VERSION 5.8 ;
BUSBITCHARS "[]" ;
DIVIDERCHAR "/" ;
UNITS
    DATABASE MICRONS 1000 ;
END UNITS

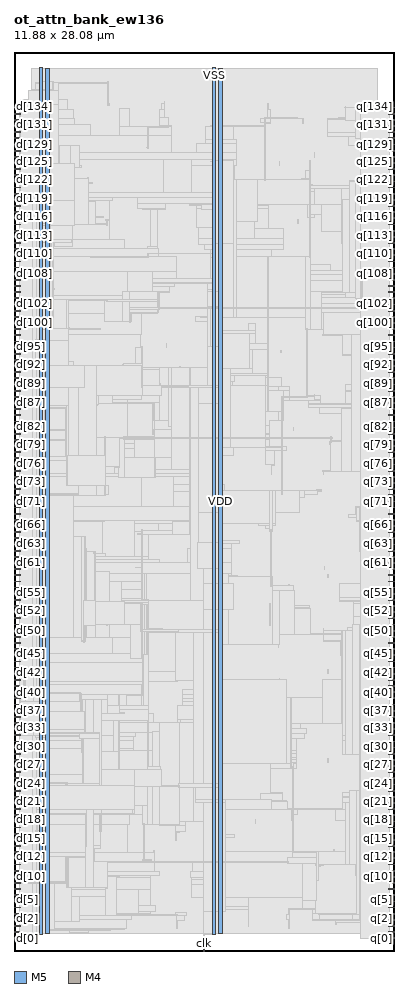
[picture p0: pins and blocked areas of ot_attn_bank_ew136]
MACRO ot_attn_bank_ew136
  FOREIGN ot_attn_bank_ew136 0 0 ;
  CLASS BLOCK ;
  SIZE 11.88 BY 28.08 ;
  PIN clk
    DIRECTION INPUT ;
    USE SIGNAL ;
    PORT
      LAYER M5 ;
        RECT  5.904 0 5.928 0.192 ;
    END
  END clk
  PIN d[0]
    DIRECTION INPUT ;
    USE SIGNAL ;
    PORT
      LAYER M4 ;
        RECT  0 0.384 0.192 0.408 ;
    END
  END d[0]
  PIN d[100]
    DIRECTION INPUT ;
    USE SIGNAL ;
    PORT
      LAYER M4 ;
        RECT  0 19.584 0.192 19.608 ;
    END
  END d[100]
  PIN d[101]
    DIRECTION INPUT ;
    USE SIGNAL ;
    PORT
      LAYER M4 ;
        RECT  0 19.776 0.192 19.8 ;
    END
  END d[101]
  PIN d[102]
    DIRECTION INPUT ;
    USE SIGNAL ;
    PORT
      LAYER M4 ;
        RECT  0 19.968 0.192 19.992 ;
    END
  END d[102]
  PIN d[103]
    DIRECTION INPUT ;
    USE SIGNAL ;
    PORT
      LAYER M4 ;
        RECT  0 20.16 0.192 20.184 ;
    END
  END d[103]
  PIN d[104]
    DIRECTION INPUT ;
    USE SIGNAL ;
    PORT
      LAYER M4 ;
        RECT  0 20.352 0.192 20.376 ;
    END
  END d[104]
  PIN d[105]
    DIRECTION INPUT ;
    USE SIGNAL ;
    PORT
      LAYER M4 ;
        RECT  0 20.544 0.192 20.568 ;
    END
  END d[105]
  PIN d[106]
    DIRECTION INPUT ;
    USE SIGNAL ;
    PORT
      LAYER M4 ;
        RECT  0 20.736 0.192 20.76 ;
    END
  END d[106]
  PIN d[107]
    DIRECTION INPUT ;
    USE SIGNAL ;
    PORT
      LAYER M4 ;
        RECT  0 20.928 0.192 20.952 ;
    END
  END d[107]
  PIN d[108]
    DIRECTION INPUT ;
    USE SIGNAL ;
    PORT
      LAYER M4 ;
        RECT  0 21.12 0.192 21.144 ;
    END
  END d[108]
  PIN d[109]
    DIRECTION INPUT ;
    USE SIGNAL ;
    PORT
      LAYER M4 ;
        RECT  0 21.312 0.192 21.336 ;
    END
  END d[109]
  PIN d[10]
    DIRECTION INPUT ;
    USE SIGNAL ;
    PORT
      LAYER M4 ;
        RECT  0 2.304 0.192 2.328 ;
    END
  END d[10]
  PIN d[110]
    DIRECTION INPUT ;
    USE SIGNAL ;
    PORT
      LAYER M4 ;
        RECT  0 21.504 0.192 21.528 ;
    END
  END d[110]
  PIN d[111]
    DIRECTION INPUT ;
    USE SIGNAL ;
    PORT
      LAYER M4 ;
        RECT  0 21.696 0.192 21.72 ;
    END
  END d[111]
  PIN d[112]
    DIRECTION INPUT ;
    USE SIGNAL ;
    PORT
      LAYER M4 ;
        RECT  0 21.888 0.192 21.912 ;
    END
  END d[112]
  PIN d[113]
    DIRECTION INPUT ;
    USE SIGNAL ;
    PORT
      LAYER M4 ;
        RECT  0 22.08 0.192 22.104 ;
    END
  END d[113]
  PIN d[114]
    DIRECTION INPUT ;
    USE SIGNAL ;
    PORT
      LAYER M4 ;
        RECT  0 22.272 0.192 22.296 ;
    END
  END d[114]
  PIN d[115]
    DIRECTION INPUT ;
    USE SIGNAL ;
    PORT
      LAYER M4 ;
        RECT  0 22.464 0.192 22.488 ;
    END
  END d[115]
  PIN d[116]
    DIRECTION INPUT ;
    USE SIGNAL ;
    PORT
      LAYER M4 ;
        RECT  0 22.656 0.192 22.68 ;
    END
  END d[116]
  PIN d[117]
    DIRECTION INPUT ;
    USE SIGNAL ;
    PORT
      LAYER M4 ;
        RECT  0 22.848 0.192 22.872 ;
    END
  END d[117]
  PIN d[118]
    DIRECTION INPUT ;
    USE SIGNAL ;
    PORT
      LAYER M4 ;
        RECT  0 23.04 0.192 23.064 ;
    END
  END d[118]
  PIN d[119]
    DIRECTION INPUT ;
    USE SIGNAL ;
    PORT
      LAYER M4 ;
        RECT  0 23.232 0.192 23.256 ;
    END
  END d[119]
  PIN d[11]
    DIRECTION INPUT ;
    USE SIGNAL ;
    PORT
      LAYER M4 ;
        RECT  0 2.496 0.192 2.52 ;
    END
  END d[11]
  PIN d[120]
    DIRECTION INPUT ;
    USE SIGNAL ;
    PORT
      LAYER M4 ;
        RECT  0 23.424 0.192 23.448 ;
    END
  END d[120]
  PIN d[121]
    DIRECTION INPUT ;
    USE SIGNAL ;
    PORT
      LAYER M4 ;
        RECT  0 23.616 0.192 23.64 ;
    END
  END d[121]
  PIN d[122]
    DIRECTION INPUT ;
    USE SIGNAL ;
    PORT
      LAYER M4 ;
        RECT  0 23.808 0.192 23.832 ;
    END
  END d[122]
  PIN d[123]
    DIRECTION INPUT ;
    USE SIGNAL ;
    PORT
      LAYER M4 ;
        RECT  0 24 0.192 24.024 ;
    END
  END d[123]
  PIN d[124]
    DIRECTION INPUT ;
    USE SIGNAL ;
    PORT
      LAYER M4 ;
        RECT  0 24.192 0.192 24.216 ;
    END
  END d[124]
  PIN d[125]
    DIRECTION INPUT ;
    USE SIGNAL ;
    PORT
      LAYER M4 ;
        RECT  0 24.384 0.192 24.408 ;
    END
  END d[125]
  PIN d[126]
    DIRECTION INPUT ;
    USE SIGNAL ;
    PORT
      LAYER M4 ;
        RECT  0 24.576 0.192 24.6 ;
    END
  END d[126]
  PIN d[127]
    DIRECTION INPUT ;
    USE SIGNAL ;
    PORT
      LAYER M4 ;
        RECT  0 24.768 0.192 24.792 ;
    END
  END d[127]
  PIN d[128]
    DIRECTION INPUT ;
    USE SIGNAL ;
    PORT
      LAYER M4 ;
        RECT  0 24.96 0.192 24.984 ;
    END
  END d[128]
  PIN d[129]
    DIRECTION INPUT ;
    USE SIGNAL ;
    PORT
      LAYER M4 ;
        RECT  0 25.152 0.192 25.176 ;
    END
  END d[129]
  PIN d[12]
    DIRECTION INPUT ;
    USE SIGNAL ;
    PORT
      LAYER M4 ;
        RECT  0 2.688 0.192 2.712 ;
    END
  END d[12]
  PIN d[130]
    DIRECTION INPUT ;
    USE SIGNAL ;
    PORT
      LAYER M4 ;
        RECT  0 25.344 0.192 25.368 ;
    END
  END d[130]
  PIN d[131]
    DIRECTION INPUT ;
    USE SIGNAL ;
    PORT
      LAYER M4 ;
        RECT  0 25.536 0.192 25.56 ;
    END
  END d[131]
  PIN d[132]
    DIRECTION INPUT ;
    USE SIGNAL ;
    PORT
      LAYER M4 ;
        RECT  0 25.728 0.192 25.752 ;
    END
  END d[132]
  PIN d[133]
    DIRECTION INPUT ;
    USE SIGNAL ;
    PORT
      LAYER M4 ;
        RECT  0 25.92 0.192 25.944 ;
    END
  END d[133]
  PIN d[134]
    DIRECTION INPUT ;
    USE SIGNAL ;
    PORT
      LAYER M4 ;
        RECT  0 26.112 0.192 26.136 ;
    END
  END d[134]
  PIN d[135]
    DIRECTION INPUT ;
    USE SIGNAL ;
    PORT
      LAYER M4 ;
        RECT  0 26.304 0.192 26.328 ;
    END
  END d[135]
  PIN d[13]
    DIRECTION INPUT ;
    USE SIGNAL ;
    PORT
      LAYER M4 ;
        RECT  0 2.88 0.192 2.904 ;
    END
  END d[13]
  PIN d[14]
    DIRECTION INPUT ;
    USE SIGNAL ;
    PORT
      LAYER M4 ;
        RECT  0 3.072 0.192 3.096 ;
    END
  END d[14]
  PIN d[15]
    DIRECTION INPUT ;
    USE SIGNAL ;
    PORT
      LAYER M4 ;
        RECT  0 3.264 0.192 3.288 ;
    END
  END d[15]
  PIN d[16]
    DIRECTION INPUT ;
    USE SIGNAL ;
    PORT
      LAYER M4 ;
        RECT  0 3.456 0.192 3.48 ;
    END
  END d[16]
  PIN d[17]
    DIRECTION INPUT ;
    USE SIGNAL ;
    PORT
      LAYER M4 ;
        RECT  0 3.648 0.192 3.672 ;
    END
  END d[17]
  PIN d[18]
    DIRECTION INPUT ;
    USE SIGNAL ;
    PORT
      LAYER M4 ;
        RECT  0 3.84 0.192 3.864 ;
    END
  END d[18]
  PIN d[19]
    DIRECTION INPUT ;
    USE SIGNAL ;
    PORT
      LAYER M4 ;
        RECT  0 4.032 0.192 4.056 ;
    END
  END d[19]
  PIN d[1]
    DIRECTION INPUT ;
    USE SIGNAL ;
    PORT
      LAYER M4 ;
        RECT  0 0.576 0.192 0.6 ;
    END
  END d[1]
  PIN d[20]
    DIRECTION INPUT ;
    USE SIGNAL ;
    PORT
      LAYER M4 ;
        RECT  0 4.224 0.192 4.248 ;
    END
  END d[20]
  PIN d[21]
    DIRECTION INPUT ;
    USE SIGNAL ;
    PORT
      LAYER M4 ;
        RECT  0 4.416 0.192 4.44 ;
    END
  END d[21]
  PIN d[22]
    DIRECTION INPUT ;
    USE SIGNAL ;
    PORT
      LAYER M4 ;
        RECT  0 4.608 0.192 4.632 ;
    END
  END d[22]
  PIN d[23]
    DIRECTION INPUT ;
    USE SIGNAL ;
    PORT
      LAYER M4 ;
        RECT  0 4.8 0.192 4.824 ;
    END
  END d[23]
  PIN d[24]
    DIRECTION INPUT ;
    USE SIGNAL ;
    PORT
      LAYER M4 ;
        RECT  0 4.992 0.192 5.016 ;
    END
  END d[24]
  PIN d[25]
    DIRECTION INPUT ;
    USE SIGNAL ;
    PORT
      LAYER M4 ;
        RECT  0 5.184 0.192 5.208 ;
    END
  END d[25]
  PIN d[26]
    DIRECTION INPUT ;
    USE SIGNAL ;
    PORT
      LAYER M4 ;
        RECT  0 5.376 0.192 5.4 ;
    END
  END d[26]
  PIN d[27]
    DIRECTION INPUT ;
    USE SIGNAL ;
    PORT
      LAYER M4 ;
        RECT  0 5.568 0.192 5.592 ;
    END
  END d[27]
  PIN d[28]
    DIRECTION INPUT ;
    USE SIGNAL ;
    PORT
      LAYER M4 ;
        RECT  0 5.76 0.192 5.784 ;
    END
  END d[28]
  PIN d[29]
    DIRECTION INPUT ;
    USE SIGNAL ;
    PORT
      LAYER M4 ;
        RECT  0 5.952 0.192 5.976 ;
    END
  END d[29]
  PIN d[2]
    DIRECTION INPUT ;
    USE SIGNAL ;
    PORT
      LAYER M4 ;
        RECT  0 0.768 0.192 0.792 ;
    END
  END d[2]
  PIN d[30]
    DIRECTION INPUT ;
    USE SIGNAL ;
    PORT
      LAYER M4 ;
        RECT  0 6.144 0.192 6.168 ;
    END
  END d[30]
  PIN d[31]
    DIRECTION INPUT ;
    USE SIGNAL ;
    PORT
      LAYER M4 ;
        RECT  0 6.336 0.192 6.36 ;
    END
  END d[31]
  PIN d[32]
    DIRECTION INPUT ;
    USE SIGNAL ;
    PORT
      LAYER M4 ;
        RECT  0 6.528 0.192 6.552 ;
    END
  END d[32]
  PIN d[33]
    DIRECTION INPUT ;
    USE SIGNAL ;
    PORT
      LAYER M4 ;
        RECT  0 6.72 0.192 6.744 ;
    END
  END d[33]
  PIN d[34]
    DIRECTION INPUT ;
    USE SIGNAL ;
    PORT
      LAYER M4 ;
        RECT  0 6.912 0.192 6.936 ;
    END
  END d[34]
  PIN d[35]
    DIRECTION INPUT ;
    USE SIGNAL ;
    PORT
      LAYER M4 ;
        RECT  0 7.104 0.192 7.128 ;
    END
  END d[35]
  PIN d[36]
    DIRECTION INPUT ;
    USE SIGNAL ;
    PORT
      LAYER M4 ;
        RECT  0 7.296 0.192 7.32 ;
    END
  END d[36]
  PIN d[37]
    DIRECTION INPUT ;
    USE SIGNAL ;
    PORT
      LAYER M4 ;
        RECT  0 7.488 0.192 7.512 ;
    END
  END d[37]
  PIN d[38]
    DIRECTION INPUT ;
    USE SIGNAL ;
    PORT
      LAYER M4 ;
        RECT  0 7.68 0.192 7.704 ;
    END
  END d[38]
  PIN d[39]
    DIRECTION INPUT ;
    USE SIGNAL ;
    PORT
      LAYER M4 ;
        RECT  0 7.872 0.192 7.896 ;
    END
  END d[39]
  PIN d[3]
    DIRECTION INPUT ;
    USE SIGNAL ;
    PORT
      LAYER M4 ;
        RECT  0 0.96 0.192 0.984 ;
    END
  END d[3]
  PIN d[40]
    DIRECTION INPUT ;
    USE SIGNAL ;
    PORT
      LAYER M4 ;
        RECT  0 8.064 0.192 8.088 ;
    END
  END d[40]
  PIN d[41]
    DIRECTION INPUT ;
    USE SIGNAL ;
    PORT
      LAYER M4 ;
        RECT  0 8.256 0.192 8.28 ;
    END
  END d[41]
  PIN d[42]
    DIRECTION INPUT ;
    USE SIGNAL ;
    PORT
      LAYER M4 ;
        RECT  0 8.448 0.192 8.472 ;
    END
  END d[42]
  PIN d[43]
    DIRECTION INPUT ;
    USE SIGNAL ;
    PORT
      LAYER M4 ;
        RECT  0 8.64 0.192 8.664 ;
    END
  END d[43]
  PIN d[44]
    DIRECTION INPUT ;
    USE SIGNAL ;
    PORT
      LAYER M4 ;
        RECT  0 8.832 0.192 8.856 ;
    END
  END d[44]
  PIN d[45]
    DIRECTION INPUT ;
    USE SIGNAL ;
    PORT
      LAYER M4 ;
        RECT  0 9.024 0.192 9.048 ;
    END
  END d[45]
  PIN d[46]
    DIRECTION INPUT ;
    USE SIGNAL ;
    PORT
      LAYER M4 ;
        RECT  0 9.216 0.192 9.24 ;
    END
  END d[46]
  PIN d[47]
    DIRECTION INPUT ;
    USE SIGNAL ;
    PORT
      LAYER M4 ;
        RECT  0 9.408 0.192 9.432 ;
    END
  END d[47]
  PIN d[48]
    DIRECTION INPUT ;
    USE SIGNAL ;
    PORT
      LAYER M4 ;
        RECT  0 9.6 0.192 9.624 ;
    END
  END d[48]
  PIN d[49]
    DIRECTION INPUT ;
    USE SIGNAL ;
    PORT
      LAYER M4 ;
        RECT  0 9.792 0.192 9.816 ;
    END
  END d[49]
  PIN d[4]
    DIRECTION INPUT ;
    USE SIGNAL ;
    PORT
      LAYER M4 ;
        RECT  0 1.152 0.192 1.176 ;
    END
  END d[4]
  PIN d[50]
    DIRECTION INPUT ;
    USE SIGNAL ;
    PORT
      LAYER M4 ;
        RECT  0 9.984 0.192 10.008 ;
    END
  END d[50]
  PIN d[51]
    DIRECTION INPUT ;
    USE SIGNAL ;
    PORT
      LAYER M4 ;
        RECT  0 10.176 0.192 10.2 ;
    END
  END d[51]
  PIN d[52]
    DIRECTION INPUT ;
    USE SIGNAL ;
    PORT
      LAYER M4 ;
        RECT  0 10.368 0.192 10.392 ;
    END
  END d[52]
  PIN d[53]
    DIRECTION INPUT ;
    USE SIGNAL ;
    PORT
      LAYER M4 ;
        RECT  0 10.56 0.192 10.584 ;
    END
  END d[53]
  PIN d[54]
    DIRECTION INPUT ;
    USE SIGNAL ;
    PORT
      LAYER M4 ;
        RECT  0 10.752 0.192 10.776 ;
    END
  END d[54]
  PIN d[55]
    DIRECTION INPUT ;
    USE SIGNAL ;
    PORT
      LAYER M4 ;
        RECT  0 10.944 0.192 10.968 ;
    END
  END d[55]
  PIN d[56]
    DIRECTION INPUT ;
    USE SIGNAL ;
    PORT
      LAYER M4 ;
        RECT  0 11.136 0.192 11.16 ;
    END
  END d[56]
  PIN d[57]
    DIRECTION INPUT ;
    USE SIGNAL ;
    PORT
      LAYER M4 ;
        RECT  0 11.328 0.192 11.352 ;
    END
  END d[57]
  PIN d[58]
    DIRECTION INPUT ;
    USE SIGNAL ;
    PORT
      LAYER M4 ;
        RECT  0 11.52 0.192 11.544 ;
    END
  END d[58]
  PIN d[59]
    DIRECTION INPUT ;
    USE SIGNAL ;
    PORT
      LAYER M4 ;
        RECT  0 11.712 0.192 11.736 ;
    END
  END d[59]
  PIN d[5]
    DIRECTION INPUT ;
    USE SIGNAL ;
    PORT
      LAYER M4 ;
        RECT  0 1.344 0.192 1.368 ;
    END
  END d[5]
  PIN d[60]
    DIRECTION INPUT ;
    USE SIGNAL ;
    PORT
      LAYER M4 ;
        RECT  0 11.904 0.192 11.928 ;
    END
  END d[60]
  PIN d[61]
    DIRECTION INPUT ;
    USE SIGNAL ;
    PORT
      LAYER M4 ;
        RECT  0 12.096 0.192 12.12 ;
    END
  END d[61]
  PIN d[62]
    DIRECTION INPUT ;
    USE SIGNAL ;
    PORT
      LAYER M4 ;
        RECT  0 12.288 0.192 12.312 ;
    END
  END d[62]
  PIN d[63]
    DIRECTION INPUT ;
    USE SIGNAL ;
    PORT
      LAYER M4 ;
        RECT  0 12.48 0.192 12.504 ;
    END
  END d[63]
  PIN d[64]
    DIRECTION INPUT ;
    USE SIGNAL ;
    PORT
      LAYER M4 ;
        RECT  0 12.672 0.192 12.696 ;
    END
  END d[64]
  PIN d[65]
    DIRECTION INPUT ;
    USE SIGNAL ;
    PORT
      LAYER M4 ;
        RECT  0 12.864 0.192 12.888 ;
    END
  END d[65]
  PIN d[66]
    DIRECTION INPUT ;
    USE SIGNAL ;
    PORT
      LAYER M4 ;
        RECT  0 13.056 0.192 13.08 ;
    END
  END d[66]
  PIN d[67]
    DIRECTION INPUT ;
    USE SIGNAL ;
    PORT
      LAYER M4 ;
        RECT  0 13.248 0.192 13.272 ;
    END
  END d[67]
  PIN d[68]
    DIRECTION INPUT ;
    USE SIGNAL ;
    PORT
      LAYER M4 ;
        RECT  0 13.44 0.192 13.464 ;
    END
  END d[68]
  PIN d[69]
    DIRECTION INPUT ;
    USE SIGNAL ;
    PORT
      LAYER M4 ;
        RECT  0 13.632 0.192 13.656 ;
    END
  END d[69]
  PIN d[6]
    DIRECTION INPUT ;
    USE SIGNAL ;
    PORT
      LAYER M4 ;
        RECT  0 1.536 0.192 1.56 ;
    END
  END d[6]
  PIN d[70]
    DIRECTION INPUT ;
    USE SIGNAL ;
    PORT
      LAYER M4 ;
        RECT  0 13.824 0.192 13.848 ;
    END
  END d[70]
  PIN d[71]
    DIRECTION INPUT ;
    USE SIGNAL ;
    PORT
      LAYER M4 ;
        RECT  0 14.016 0.192 14.04 ;
    END
  END d[71]
  PIN d[72]
    DIRECTION INPUT ;
    USE SIGNAL ;
    PORT
      LAYER M4 ;
        RECT  0 14.208 0.192 14.232 ;
    END
  END d[72]
  PIN d[73]
    DIRECTION INPUT ;
    USE SIGNAL ;
    PORT
      LAYER M4 ;
        RECT  0 14.4 0.192 14.424 ;
    END
  END d[73]
  PIN d[74]
    DIRECTION INPUT ;
    USE SIGNAL ;
    PORT
      LAYER M4 ;
        RECT  0 14.592 0.192 14.616 ;
    END
  END d[74]
  PIN d[75]
    DIRECTION INPUT ;
    USE SIGNAL ;
    PORT
      LAYER M4 ;
        RECT  0 14.784 0.192 14.808 ;
    END
  END d[75]
  PIN d[76]
    DIRECTION INPUT ;
    USE SIGNAL ;
    PORT
      LAYER M4 ;
        RECT  0 14.976 0.192 15 ;
    END
  END d[76]
  PIN d[77]
    DIRECTION INPUT ;
    USE SIGNAL ;
    PORT
      LAYER M4 ;
        RECT  0 15.168 0.192 15.192 ;
    END
  END d[77]
  PIN d[78]
    DIRECTION INPUT ;
    USE SIGNAL ;
    PORT
      LAYER M4 ;
        RECT  0 15.36 0.192 15.384 ;
    END
  END d[78]
  PIN d[79]
    DIRECTION INPUT ;
    USE SIGNAL ;
    PORT
      LAYER M4 ;
        RECT  0 15.552 0.192 15.576 ;
    END
  END d[79]
  PIN d[7]
    DIRECTION INPUT ;
    USE SIGNAL ;
    PORT
      LAYER M4 ;
        RECT  0 1.728 0.192 1.752 ;
    END
  END d[7]
  PIN d[80]
    DIRECTION INPUT ;
    USE SIGNAL ;
    PORT
      LAYER M4 ;
        RECT  0 15.744 0.192 15.768 ;
    END
  END d[80]
  PIN d[81]
    DIRECTION INPUT ;
    USE SIGNAL ;
    PORT
      LAYER M4 ;
        RECT  0 15.936 0.192 15.96 ;
    END
  END d[81]
  PIN d[82]
    DIRECTION INPUT ;
    USE SIGNAL ;
    PORT
      LAYER M4 ;
        RECT  0 16.128 0.192 16.152 ;
    END
  END d[82]
  PIN d[83]
    DIRECTION INPUT ;
    USE SIGNAL ;
    PORT
      LAYER M4 ;
        RECT  0 16.32 0.192 16.344 ;
    END
  END d[83]
  PIN d[84]
    DIRECTION INPUT ;
    USE SIGNAL ;
    PORT
      LAYER M4 ;
        RECT  0 16.512 0.192 16.536 ;
    END
  END d[84]
  PIN d[85]
    DIRECTION INPUT ;
    USE SIGNAL ;
    PORT
      LAYER M4 ;
        RECT  0 16.704 0.192 16.728 ;
    END
  END d[85]
  PIN d[86]
    DIRECTION INPUT ;
    USE SIGNAL ;
    PORT
      LAYER M4 ;
        RECT  0 16.896 0.192 16.92 ;
    END
  END d[86]
  PIN d[87]
    DIRECTION INPUT ;
    USE SIGNAL ;
    PORT
      LAYER M4 ;
        RECT  0 17.088 0.192 17.112 ;
    END
  END d[87]
  PIN d[88]
    DIRECTION INPUT ;
    USE SIGNAL ;
    PORT
      LAYER M4 ;
        RECT  0 17.28 0.192 17.304 ;
    END
  END d[88]
  PIN d[89]
    DIRECTION INPUT ;
    USE SIGNAL ;
    PORT
      LAYER M4 ;
        RECT  0 17.472 0.192 17.496 ;
    END
  END d[89]
  PIN d[8]
    DIRECTION INPUT ;
    USE SIGNAL ;
    PORT
      LAYER M4 ;
        RECT  0 1.92 0.192 1.944 ;
    END
  END d[8]
  PIN d[90]
    DIRECTION INPUT ;
    USE SIGNAL ;
    PORT
      LAYER M4 ;
        RECT  0 17.664 0.192 17.688 ;
    END
  END d[90]
  PIN d[91]
    DIRECTION INPUT ;
    USE SIGNAL ;
    PORT
      LAYER M4 ;
        RECT  0 17.856 0.192 17.88 ;
    END
  END d[91]
  PIN d[92]
    DIRECTION INPUT ;
    USE SIGNAL ;
    PORT
      LAYER M4 ;
        RECT  0 18.048 0.192 18.072 ;
    END
  END d[92]
  PIN d[93]
    DIRECTION INPUT ;
    USE SIGNAL ;
    PORT
      LAYER M4 ;
        RECT  0 18.24 0.192 18.264 ;
    END
  END d[93]
  PIN d[94]
    DIRECTION INPUT ;
    USE SIGNAL ;
    PORT
      LAYER M4 ;
        RECT  0 18.432 0.192 18.456 ;
    END
  END d[94]
  PIN d[95]
    DIRECTION INPUT ;
    USE SIGNAL ;
    PORT
      LAYER M4 ;
        RECT  0 18.624 0.192 18.648 ;
    END
  END d[95]
  PIN d[96]
    DIRECTION INPUT ;
    USE SIGNAL ;
    PORT
      LAYER M4 ;
        RECT  0 18.816 0.192 18.84 ;
    END
  END d[96]
  PIN d[97]
    DIRECTION INPUT ;
    USE SIGNAL ;
    PORT
      LAYER M4 ;
        RECT  0 19.008 0.192 19.032 ;
    END
  END d[97]
  PIN d[98]
    DIRECTION INPUT ;
    USE SIGNAL ;
    PORT
      LAYER M4 ;
        RECT  0 19.2 0.192 19.224 ;
    END
  END d[98]
  PIN d[99]
    DIRECTION INPUT ;
    USE SIGNAL ;
    PORT
      LAYER M4 ;
        RECT  0 19.392 0.192 19.416 ;
    END
  END d[99]
  PIN d[9]
    DIRECTION INPUT ;
    USE SIGNAL ;
    PORT
      LAYER M4 ;
        RECT  0 2.112 0.192 2.136 ;
    END
  END d[9]
  PIN q[0]
    DIRECTION OUTPUT ;
    USE SIGNAL ;
    PORT
      LAYER M4 ;
        RECT  11.688 0.384 11.88 0.408 ;
    END
  END q[0]
  PIN q[100]
    DIRECTION OUTPUT ;
    USE SIGNAL ;
    PORT
      LAYER M4 ;
        RECT  11.688 19.584 11.88 19.608 ;
    END
  END q[100]
  PIN q[101]
    DIRECTION OUTPUT ;
    USE SIGNAL ;
    PORT
      LAYER M4 ;
        RECT  11.688 19.776 11.88 19.8 ;
    END
  END q[101]
  PIN q[102]
    DIRECTION OUTPUT ;
    USE SIGNAL ;
    PORT
      LAYER M4 ;
        RECT  11.688 19.968 11.88 19.992 ;
    END
  END q[102]
  PIN q[103]
    DIRECTION OUTPUT ;
    USE SIGNAL ;
    PORT
      LAYER M4 ;
        RECT  11.688 20.16 11.88 20.184 ;
    END
  END q[103]
  PIN q[104]
    DIRECTION OUTPUT ;
    USE SIGNAL ;
    PORT
      LAYER M4 ;
        RECT  11.688 20.352 11.88 20.376 ;
    END
  END q[104]
  PIN q[105]
    DIRECTION OUTPUT ;
    USE SIGNAL ;
    PORT
      LAYER M4 ;
        RECT  11.688 20.544 11.88 20.568 ;
    END
  END q[105]
  PIN q[106]
    DIRECTION OUTPUT ;
    USE SIGNAL ;
    PORT
      LAYER M4 ;
        RECT  11.688 20.736 11.88 20.76 ;
    END
  END q[106]
  PIN q[107]
    DIRECTION OUTPUT ;
    USE SIGNAL ;
    PORT
      LAYER M4 ;
        RECT  11.688 20.928 11.88 20.952 ;
    END
  END q[107]
  PIN q[108]
    DIRECTION OUTPUT ;
    USE SIGNAL ;
    PORT
      LAYER M4 ;
        RECT  11.688 21.12 11.88 21.144 ;
    END
  END q[108]
  PIN q[109]
    DIRECTION OUTPUT ;
    USE SIGNAL ;
    PORT
      LAYER M4 ;
        RECT  11.688 21.312 11.88 21.336 ;
    END
  END q[109]
  PIN q[10]
    DIRECTION OUTPUT ;
    USE SIGNAL ;
    PORT
      LAYER M4 ;
        RECT  11.688 2.304 11.88 2.328 ;
    END
  END q[10]
  PIN q[110]
    DIRECTION OUTPUT ;
    USE SIGNAL ;
    PORT
      LAYER M4 ;
        RECT  11.688 21.504 11.88 21.528 ;
    END
  END q[110]
  PIN q[111]
    DIRECTION OUTPUT ;
    USE SIGNAL ;
    PORT
      LAYER M4 ;
        RECT  11.688 21.696 11.88 21.72 ;
    END
  END q[111]
  PIN q[112]
    DIRECTION OUTPUT ;
    USE SIGNAL ;
    PORT
      LAYER M4 ;
        RECT  11.688 21.888 11.88 21.912 ;
    END
  END q[112]
  PIN q[113]
    DIRECTION OUTPUT ;
    USE SIGNAL ;
    PORT
      LAYER M4 ;
        RECT  11.688 22.08 11.88 22.104 ;
    END
  END q[113]
  PIN q[114]
    DIRECTION OUTPUT ;
    USE SIGNAL ;
    PORT
      LAYER M4 ;
        RECT  11.688 22.272 11.88 22.296 ;
    END
  END q[114]
  PIN q[115]
    DIRECTION OUTPUT ;
    USE SIGNAL ;
    PORT
      LAYER M4 ;
        RECT  11.688 22.464 11.88 22.488 ;
    END
  END q[115]
  PIN q[116]
    DIRECTION OUTPUT ;
    USE SIGNAL ;
    PORT
      LAYER M4 ;
        RECT  11.688 22.656 11.88 22.68 ;
    END
  END q[116]
  PIN q[117]
    DIRECTION OUTPUT ;
    USE SIGNAL ;
    PORT
      LAYER M4 ;
        RECT  11.688 22.848 11.88 22.872 ;
    END
  END q[117]
  PIN q[118]
    DIRECTION OUTPUT ;
    USE SIGNAL ;
    PORT
      LAYER M4 ;
        RECT  11.688 23.04 11.88 23.064 ;
    END
  END q[118]
  PIN q[119]
    DIRECTION OUTPUT ;
    USE SIGNAL ;
    PORT
      LAYER M4 ;
        RECT  11.688 23.232 11.88 23.256 ;
    END
  END q[119]
  PIN q[11]
    DIRECTION OUTPUT ;
    USE SIGNAL ;
    PORT
      LAYER M4 ;
        RECT  11.688 2.496 11.88 2.52 ;
    END
  END q[11]
  PIN q[120]
    DIRECTION OUTPUT ;
    USE SIGNAL ;
    PORT
      LAYER M4 ;
        RECT  11.688 23.424 11.88 23.448 ;
    END
  END q[120]
  PIN q[121]
    DIRECTION OUTPUT ;
    USE SIGNAL ;
    PORT
      LAYER M4 ;
        RECT  11.688 23.616 11.88 23.64 ;
    END
  END q[121]
  PIN q[122]
    DIRECTION OUTPUT ;
    USE SIGNAL ;
    PORT
      LAYER M4 ;
        RECT  11.688 23.808 11.88 23.832 ;
    END
  END q[122]
  PIN q[123]
    DIRECTION OUTPUT ;
    USE SIGNAL ;
    PORT
      LAYER M4 ;
        RECT  11.688 24 11.88 24.024 ;
    END
  END q[123]
  PIN q[124]
    DIRECTION OUTPUT ;
    USE SIGNAL ;
    PORT
      LAYER M4 ;
        RECT  11.688 24.192 11.88 24.216 ;
    END
  END q[124]
  PIN q[125]
    DIRECTION OUTPUT ;
    USE SIGNAL ;
    PORT
      LAYER M4 ;
        RECT  11.688 24.384 11.88 24.408 ;
    END
  END q[125]
  PIN q[126]
    DIRECTION OUTPUT ;
    USE SIGNAL ;
    PORT
      LAYER M4 ;
        RECT  11.688 24.576 11.88 24.6 ;
    END
  END q[126]
  PIN q[127]
    DIRECTION OUTPUT ;
    USE SIGNAL ;
    PORT
      LAYER M4 ;
        RECT  11.688 24.768 11.88 24.792 ;
    END
  END q[127]
  PIN q[128]
    DIRECTION OUTPUT ;
    USE SIGNAL ;
    PORT
      LAYER M4 ;
        RECT  11.688 24.96 11.88 24.984 ;
    END
  END q[128]
  PIN q[129]
    DIRECTION OUTPUT ;
    USE SIGNAL ;
    PORT
      LAYER M4 ;
        RECT  11.688 25.152 11.88 25.176 ;
    END
  END q[129]
  PIN q[12]
    DIRECTION OUTPUT ;
    USE SIGNAL ;
    PORT
      LAYER M4 ;
        RECT  11.688 2.688 11.88 2.712 ;
    END
  END q[12]
  PIN q[130]
    DIRECTION OUTPUT ;
    USE SIGNAL ;
    PORT
      LAYER M4 ;
        RECT  11.688 25.344 11.88 25.368 ;
    END
  END q[130]
  PIN q[131]
    DIRECTION OUTPUT ;
    USE SIGNAL ;
    PORT
      LAYER M4 ;
        RECT  11.688 25.536 11.88 25.56 ;
    END
  END q[131]
  PIN q[132]
    DIRECTION OUTPUT ;
    USE SIGNAL ;
    PORT
      LAYER M4 ;
        RECT  11.688 25.728 11.88 25.752 ;
    END
  END q[132]
  PIN q[133]
    DIRECTION OUTPUT ;
    USE SIGNAL ;
    PORT
      LAYER M4 ;
        RECT  11.688 25.92 11.88 25.944 ;
    END
  END q[133]
  PIN q[134]
    DIRECTION OUTPUT ;
    USE SIGNAL ;
    PORT
      LAYER M4 ;
        RECT  11.688 26.112 11.88 26.136 ;
    END
  END q[134]
  PIN q[135]
    DIRECTION OUTPUT ;
    USE SIGNAL ;
    PORT
      LAYER M4 ;
        RECT  11.688 26.304 11.88 26.328 ;
    END
  END q[135]
  PIN q[13]
    DIRECTION OUTPUT ;
    USE SIGNAL ;
    PORT
      LAYER M4 ;
        RECT  11.688 2.88 11.88 2.904 ;
    END
  END q[13]
  PIN q[14]
    DIRECTION OUTPUT ;
    USE SIGNAL ;
    PORT
      LAYER M4 ;
        RECT  11.688 3.072 11.88 3.096 ;
    END
  END q[14]
  PIN q[15]
    DIRECTION OUTPUT ;
    USE SIGNAL ;
    PORT
      LAYER M4 ;
        RECT  11.688 3.264 11.88 3.288 ;
    END
  END q[15]
  PIN q[16]
    DIRECTION OUTPUT ;
    USE SIGNAL ;
    PORT
      LAYER M4 ;
        RECT  11.688 3.456 11.88 3.48 ;
    END
  END q[16]
  PIN q[17]
    DIRECTION OUTPUT ;
    USE SIGNAL ;
    PORT
      LAYER M4 ;
        RECT  11.688 3.648 11.88 3.672 ;
    END
  END q[17]
  PIN q[18]
    DIRECTION OUTPUT ;
    USE SIGNAL ;
    PORT
      LAYER M4 ;
        RECT  11.688 3.84 11.88 3.864 ;
    END
  END q[18]
  PIN q[19]
    DIRECTION OUTPUT ;
    USE SIGNAL ;
    PORT
      LAYER M4 ;
        RECT  11.688 4.032 11.88 4.056 ;
    END
  END q[19]
  PIN q[1]
    DIRECTION OUTPUT ;
    USE SIGNAL ;
    PORT
      LAYER M4 ;
        RECT  11.688 0.576 11.88 0.6 ;
    END
  END q[1]
  PIN q[20]
    DIRECTION OUTPUT ;
    USE SIGNAL ;
    PORT
      LAYER M4 ;
        RECT  11.688 4.224 11.88 4.248 ;
    END
  END q[20]
  PIN q[21]
    DIRECTION OUTPUT ;
    USE SIGNAL ;
    PORT
      LAYER M4 ;
        RECT  11.688 4.416 11.88 4.44 ;
    END
  END q[21]
  PIN q[22]
    DIRECTION OUTPUT ;
    USE SIGNAL ;
    PORT
      LAYER M4 ;
        RECT  11.688 4.608 11.88 4.632 ;
    END
  END q[22]
  PIN q[23]
    DIRECTION OUTPUT ;
    USE SIGNAL ;
    PORT
      LAYER M4 ;
        RECT  11.688 4.8 11.88 4.824 ;
    END
  END q[23]
  PIN q[24]
    DIRECTION OUTPUT ;
    USE SIGNAL ;
    PORT
      LAYER M4 ;
        RECT  11.688 4.992 11.88 5.016 ;
    END
  END q[24]
  PIN q[25]
    DIRECTION OUTPUT ;
    USE SIGNAL ;
    PORT
      LAYER M4 ;
        RECT  11.688 5.184 11.88 5.208 ;
    END
  END q[25]
  PIN q[26]
    DIRECTION OUTPUT ;
    USE SIGNAL ;
    PORT
      LAYER M4 ;
        RECT  11.688 5.376 11.88 5.4 ;
    END
  END q[26]
  PIN q[27]
    DIRECTION OUTPUT ;
    USE SIGNAL ;
    PORT
      LAYER M4 ;
        RECT  11.688 5.568 11.88 5.592 ;
    END
  END q[27]
  PIN q[28]
    DIRECTION OUTPUT ;
    USE SIGNAL ;
    PORT
      LAYER M4 ;
        RECT  11.688 5.76 11.88 5.784 ;
    END
  END q[28]
  PIN q[29]
    DIRECTION OUTPUT ;
    USE SIGNAL ;
    PORT
      LAYER M4 ;
        RECT  11.688 5.952 11.88 5.976 ;
    END
  END q[29]
  PIN q[2]
    DIRECTION OUTPUT ;
    USE SIGNAL ;
    PORT
      LAYER M4 ;
        RECT  11.688 0.768 11.88 0.792 ;
    END
  END q[2]
  PIN q[30]
    DIRECTION OUTPUT ;
    USE SIGNAL ;
    PORT
      LAYER M4 ;
        RECT  11.688 6.144 11.88 6.168 ;
    END
  END q[30]
  PIN q[31]
    DIRECTION OUTPUT ;
    USE SIGNAL ;
    PORT
      LAYER M4 ;
        RECT  11.688 6.336 11.88 6.36 ;
    END
  END q[31]
  PIN q[32]
    DIRECTION OUTPUT ;
    USE SIGNAL ;
    PORT
      LAYER M4 ;
        RECT  11.688 6.528 11.88 6.552 ;
    END
  END q[32]
  PIN q[33]
    DIRECTION OUTPUT ;
    USE SIGNAL ;
    PORT
      LAYER M4 ;
        RECT  11.688 6.72 11.88 6.744 ;
    END
  END q[33]
  PIN q[34]
    DIRECTION OUTPUT ;
    USE SIGNAL ;
    PORT
      LAYER M4 ;
        RECT  11.688 6.912 11.88 6.936 ;
    END
  END q[34]
  PIN q[35]
    DIRECTION OUTPUT ;
    USE SIGNAL ;
    PORT
      LAYER M4 ;
        RECT  11.688 7.104 11.88 7.128 ;
    END
  END q[35]
  PIN q[36]
    DIRECTION OUTPUT ;
    USE SIGNAL ;
    PORT
      LAYER M4 ;
        RECT  11.688 7.296 11.88 7.32 ;
    END
  END q[36]
  PIN q[37]
    DIRECTION OUTPUT ;
    USE SIGNAL ;
    PORT
      LAYER M4 ;
        RECT  11.688 7.488 11.88 7.512 ;
    END
  END q[37]
  PIN q[38]
    DIRECTION OUTPUT ;
    USE SIGNAL ;
    PORT
      LAYER M4 ;
        RECT  11.688 7.68 11.88 7.704 ;
    END
  END q[38]
  PIN q[39]
    DIRECTION OUTPUT ;
    USE SIGNAL ;
    PORT
      LAYER M4 ;
        RECT  11.688 7.872 11.88 7.896 ;
    END
  END q[39]
  PIN q[3]
    DIRECTION OUTPUT ;
    USE SIGNAL ;
    PORT
      LAYER M4 ;
        RECT  11.688 0.96 11.88 0.984 ;
    END
  END q[3]
  PIN q[40]
    DIRECTION OUTPUT ;
    USE SIGNAL ;
    PORT
      LAYER M4 ;
        RECT  11.688 8.064 11.88 8.088 ;
    END
  END q[40]
  PIN q[41]
    DIRECTION OUTPUT ;
    USE SIGNAL ;
    PORT
      LAYER M4 ;
        RECT  11.688 8.256 11.88 8.28 ;
    END
  END q[41]
  PIN q[42]
    DIRECTION OUTPUT ;
    USE SIGNAL ;
    PORT
      LAYER M4 ;
        RECT  11.688 8.448 11.88 8.472 ;
    END
  END q[42]
  PIN q[43]
    DIRECTION OUTPUT ;
    USE SIGNAL ;
    PORT
      LAYER M4 ;
        RECT  11.688 8.64 11.88 8.664 ;
    END
  END q[43]
  PIN q[44]
    DIRECTION OUTPUT ;
    USE SIGNAL ;
    PORT
      LAYER M4 ;
        RECT  11.688 8.832 11.88 8.856 ;
    END
  END q[44]
  PIN q[45]
    DIRECTION OUTPUT ;
    USE SIGNAL ;
    PORT
      LAYER M4 ;
        RECT  11.688 9.024 11.88 9.048 ;
    END
  END q[45]
  PIN q[46]
    DIRECTION OUTPUT ;
    USE SIGNAL ;
    PORT
      LAYER M4 ;
        RECT  11.688 9.216 11.88 9.24 ;
    END
  END q[46]
  PIN q[47]
    DIRECTION OUTPUT ;
    USE SIGNAL ;
    PORT
      LAYER M4 ;
        RECT  11.688 9.408 11.88 9.432 ;
    END
  END q[47]
  PIN q[48]
    DIRECTION OUTPUT ;
    USE SIGNAL ;
    PORT
      LAYER M4 ;
        RECT  11.688 9.6 11.88 9.624 ;
    END
  END q[48]
  PIN q[49]
    DIRECTION OUTPUT ;
    USE SIGNAL ;
    PORT
      LAYER M4 ;
        RECT  11.688 9.792 11.88 9.816 ;
    END
  END q[49]
  PIN q[4]
    DIRECTION OUTPUT ;
    USE SIGNAL ;
    PORT
      LAYER M4 ;
        RECT  11.688 1.152 11.88 1.176 ;
    END
  END q[4]
  PIN q[50]
    DIRECTION OUTPUT ;
    USE SIGNAL ;
    PORT
      LAYER M4 ;
        RECT  11.688 9.984 11.88 10.008 ;
    END
  END q[50]
  PIN q[51]
    DIRECTION OUTPUT ;
    USE SIGNAL ;
    PORT
      LAYER M4 ;
        RECT  11.688 10.176 11.88 10.2 ;
    END
  END q[51]
  PIN q[52]
    DIRECTION OUTPUT ;
    USE SIGNAL ;
    PORT
      LAYER M4 ;
        RECT  11.688 10.368 11.88 10.392 ;
    END
  END q[52]
  PIN q[53]
    DIRECTION OUTPUT ;
    USE SIGNAL ;
    PORT
      LAYER M4 ;
        RECT  11.688 10.56 11.88 10.584 ;
    END
  END q[53]
  PIN q[54]
    DIRECTION OUTPUT ;
    USE SIGNAL ;
    PORT
      LAYER M4 ;
        RECT  11.688 10.752 11.88 10.776 ;
    END
  END q[54]
  PIN q[55]
    DIRECTION OUTPUT ;
    USE SIGNAL ;
    PORT
      LAYER M4 ;
        RECT  11.688 10.944 11.88 10.968 ;
    END
  END q[55]
  PIN q[56]
    DIRECTION OUTPUT ;
    USE SIGNAL ;
    PORT
      LAYER M4 ;
        RECT  11.688 11.136 11.88 11.16 ;
    END
  END q[56]
  PIN q[57]
    DIRECTION OUTPUT ;
    USE SIGNAL ;
    PORT
      LAYER M4 ;
        RECT  11.688 11.328 11.88 11.352 ;
    END
  END q[57]
  PIN q[58]
    DIRECTION OUTPUT ;
    USE SIGNAL ;
    PORT
      LAYER M4 ;
        RECT  11.688 11.52 11.88 11.544 ;
    END
  END q[58]
  PIN q[59]
    DIRECTION OUTPUT ;
    USE SIGNAL ;
    PORT
      LAYER M4 ;
        RECT  11.688 11.712 11.88 11.736 ;
    END
  END q[59]
  PIN q[5]
    DIRECTION OUTPUT ;
    USE SIGNAL ;
    PORT
      LAYER M4 ;
        RECT  11.688 1.344 11.88 1.368 ;
    END
  END q[5]
  PIN q[60]
    DIRECTION OUTPUT ;
    USE SIGNAL ;
    PORT
      LAYER M4 ;
        RECT  11.688 11.904 11.88 11.928 ;
    END
  END q[60]
  PIN q[61]
    DIRECTION OUTPUT ;
    USE SIGNAL ;
    PORT
      LAYER M4 ;
        RECT  11.688 12.096 11.88 12.12 ;
    END
  END q[61]
  PIN q[62]
    DIRECTION OUTPUT ;
    USE SIGNAL ;
    PORT
      LAYER M4 ;
        RECT  11.688 12.288 11.88 12.312 ;
    END
  END q[62]
  PIN q[63]
    DIRECTION OUTPUT ;
    USE SIGNAL ;
    PORT
      LAYER M4 ;
        RECT  11.688 12.48 11.88 12.504 ;
    END
  END q[63]
  PIN q[64]
    DIRECTION OUTPUT ;
    USE SIGNAL ;
    PORT
      LAYER M4 ;
        RECT  11.688 12.672 11.88 12.696 ;
    END
  END q[64]
  PIN q[65]
    DIRECTION OUTPUT ;
    USE SIGNAL ;
    PORT
      LAYER M4 ;
        RECT  11.688 12.864 11.88 12.888 ;
    END
  END q[65]
  PIN q[66]
    DIRECTION OUTPUT ;
    USE SIGNAL ;
    PORT
      LAYER M4 ;
        RECT  11.688 13.056 11.88 13.08 ;
    END
  END q[66]
  PIN q[67]
    DIRECTION OUTPUT ;
    USE SIGNAL ;
    PORT
      LAYER M4 ;
        RECT  11.688 13.248 11.88 13.272 ;
    END
  END q[67]
  PIN q[68]
    DIRECTION OUTPUT ;
    USE SIGNAL ;
    PORT
      LAYER M4 ;
        RECT  11.688 13.44 11.88 13.464 ;
    END
  END q[68]
  PIN q[69]
    DIRECTION OUTPUT ;
    USE SIGNAL ;
    PORT
      LAYER M4 ;
        RECT  11.688 13.632 11.88 13.656 ;
    END
  END q[69]
  PIN q[6]
    DIRECTION OUTPUT ;
    USE SIGNAL ;
    PORT
      LAYER M4 ;
        RECT  11.688 1.536 11.88 1.56 ;
    END
  END q[6]
  PIN q[70]
    DIRECTION OUTPUT ;
    USE SIGNAL ;
    PORT
      LAYER M4 ;
        RECT  11.688 13.824 11.88 13.848 ;
    END
  END q[70]
  PIN q[71]
    DIRECTION OUTPUT ;
    USE SIGNAL ;
    PORT
      LAYER M4 ;
        RECT  11.688 14.016 11.88 14.04 ;
    END
  END q[71]
  PIN q[72]
    DIRECTION OUTPUT ;
    USE SIGNAL ;
    PORT
      LAYER M4 ;
        RECT  11.688 14.208 11.88 14.232 ;
    END
  END q[72]
  PIN q[73]
    DIRECTION OUTPUT ;
    USE SIGNAL ;
    PORT
      LAYER M4 ;
        RECT  11.688 14.4 11.88 14.424 ;
    END
  END q[73]
  PIN q[74]
    DIRECTION OUTPUT ;
    USE SIGNAL ;
    PORT
      LAYER M4 ;
        RECT  11.688 14.592 11.88 14.616 ;
    END
  END q[74]
  PIN q[75]
    DIRECTION OUTPUT ;
    USE SIGNAL ;
    PORT
      LAYER M4 ;
        RECT  11.688 14.784 11.88 14.808 ;
    END
  END q[75]
  PIN q[76]
    DIRECTION OUTPUT ;
    USE SIGNAL ;
    PORT
      LAYER M4 ;
        RECT  11.688 14.976 11.88 15 ;
    END
  END q[76]
  PIN q[77]
    DIRECTION OUTPUT ;
    USE SIGNAL ;
    PORT
      LAYER M4 ;
        RECT  11.688 15.168 11.88 15.192 ;
    END
  END q[77]
  PIN q[78]
    DIRECTION OUTPUT ;
    USE SIGNAL ;
    PORT
      LAYER M4 ;
        RECT  11.688 15.36 11.88 15.384 ;
    END
  END q[78]
  PIN q[79]
    DIRECTION OUTPUT ;
    USE SIGNAL ;
    PORT
      LAYER M4 ;
        RECT  11.688 15.552 11.88 15.576 ;
    END
  END q[79]
  PIN q[7]
    DIRECTION OUTPUT ;
    USE SIGNAL ;
    PORT
      LAYER M4 ;
        RECT  11.688 1.728 11.88 1.752 ;
    END
  END q[7]
  PIN q[80]
    DIRECTION OUTPUT ;
    USE SIGNAL ;
    PORT
      LAYER M4 ;
        RECT  11.688 15.744 11.88 15.768 ;
    END
  END q[80]
  PIN q[81]
    DIRECTION OUTPUT ;
    USE SIGNAL ;
    PORT
      LAYER M4 ;
        RECT  11.688 15.936 11.88 15.96 ;
    END
  END q[81]
  PIN q[82]
    DIRECTION OUTPUT ;
    USE SIGNAL ;
    PORT
      LAYER M4 ;
        RECT  11.688 16.128 11.88 16.152 ;
    END
  END q[82]
  PIN q[83]
    DIRECTION OUTPUT ;
    USE SIGNAL ;
    PORT
      LAYER M4 ;
        RECT  11.688 16.32 11.88 16.344 ;
    END
  END q[83]
  PIN q[84]
    DIRECTION OUTPUT ;
    USE SIGNAL ;
    PORT
      LAYER M4 ;
        RECT  11.688 16.512 11.88 16.536 ;
    END
  END q[84]
  PIN q[85]
    DIRECTION OUTPUT ;
    USE SIGNAL ;
    PORT
      LAYER M4 ;
        RECT  11.688 16.704 11.88 16.728 ;
    END
  END q[85]
  PIN q[86]
    DIRECTION OUTPUT ;
    USE SIGNAL ;
    PORT
      LAYER M4 ;
        RECT  11.688 16.896 11.88 16.92 ;
    END
  END q[86]
  PIN q[87]
    DIRECTION OUTPUT ;
    USE SIGNAL ;
    PORT
      LAYER M4 ;
        RECT  11.688 17.088 11.88 17.112 ;
    END
  END q[87]
  PIN q[88]
    DIRECTION OUTPUT ;
    USE SIGNAL ;
    PORT
      LAYER M4 ;
        RECT  11.688 17.28 11.88 17.304 ;
    END
  END q[88]
  PIN q[89]
    DIRECTION OUTPUT ;
    USE SIGNAL ;
    PORT
      LAYER M4 ;
        RECT  11.688 17.472 11.88 17.496 ;
    END
  END q[89]
  PIN q[8]
    DIRECTION OUTPUT ;
    USE SIGNAL ;
    PORT
      LAYER M4 ;
        RECT  11.688 1.92 11.88 1.944 ;
    END
  END q[8]
  PIN q[90]
    DIRECTION OUTPUT ;
    USE SIGNAL ;
    PORT
      LAYER M4 ;
        RECT  11.688 17.664 11.88 17.688 ;
    END
  END q[90]
  PIN q[91]
    DIRECTION OUTPUT ;
    USE SIGNAL ;
    PORT
      LAYER M4 ;
        RECT  11.688 17.856 11.88 17.88 ;
    END
  END q[91]
  PIN q[92]
    DIRECTION OUTPUT ;
    USE SIGNAL ;
    PORT
      LAYER M4 ;
        RECT  11.688 18.048 11.88 18.072 ;
    END
  END q[92]
  PIN q[93]
    DIRECTION OUTPUT ;
    USE SIGNAL ;
    PORT
      LAYER M4 ;
        RECT  11.688 18.24 11.88 18.264 ;
    END
  END q[93]
  PIN q[94]
    DIRECTION OUTPUT ;
    USE SIGNAL ;
    PORT
      LAYER M4 ;
        RECT  11.688 18.432 11.88 18.456 ;
    END
  END q[94]
  PIN q[95]
    DIRECTION OUTPUT ;
    USE SIGNAL ;
    PORT
      LAYER M4 ;
        RECT  11.688 18.624 11.88 18.648 ;
    END
  END q[95]
  PIN q[96]
    DIRECTION OUTPUT ;
    USE SIGNAL ;
    PORT
      LAYER M4 ;
        RECT  11.688 18.816 11.88 18.84 ;
    END
  END q[96]
  PIN q[97]
    DIRECTION OUTPUT ;
    USE SIGNAL ;
    PORT
      LAYER M4 ;
        RECT  11.688 19.008 11.88 19.032 ;
    END
  END q[97]
  PIN q[98]
    DIRECTION OUTPUT ;
    USE SIGNAL ;
    PORT
      LAYER M4 ;
        RECT  11.688 19.2 11.88 19.224 ;
    END
  END q[98]
  PIN q[99]
    DIRECTION OUTPUT ;
    USE SIGNAL ;
    PORT
      LAYER M4 ;
        RECT  11.688 19.392 11.88 19.416 ;
    END
  END q[99]
  PIN q[9]
    DIRECTION OUTPUT ;
    USE SIGNAL ;
    PORT
      LAYER M4 ;
        RECT  11.688 2.112 11.88 2.136 ;
    END
  END q[9]
  PIN VDD
    DIRECTION INOUT ;
    USE POWER ;
    PORT
      LAYER M5 ;
        RECT  6.372 0.531 6.492 27.549 ;
        RECT  0.972 0.531 1.092 27.549 ;
    END
  END VDD
  PIN VSS
    DIRECTION INOUT ;
    USE GROUND ;
    PORT
      LAYER M5 ;
        RECT  6.18 0.517 6.3 27.563 ;
        RECT  0.78 0.517 0.9 27.563 ;
    END
  END VSS
  OBS
    LAYER RVTN ;
     RECT  0.54 0.54 11.34 0.675 ;
     RECT  0.54 0.945 11.34 1.215 ;
     RECT  0.54 1.485 11.34 1.755 ;
     RECT  0.54 2.025 11.34 2.295 ;
     RECT  0.54 2.565 11.34 2.835 ;
     RECT  0.54 3.105 11.34 3.375 ;
     RECT  0.54 3.645 11.34 3.915 ;
     RECT  0.54 4.185 11.34 4.455 ;
     RECT  0.54 4.725 11.34 4.995 ;
     RECT  0.54 5.265 11.34 5.535 ;
     RECT  0.54 5.805 11.34 6.075 ;
     RECT  0.54 6.345 11.34 6.615 ;
     RECT  0.54 6.885 11.34 7.155 ;
     RECT  0.54 7.425 11.34 7.695 ;
     RECT  0.54 7.965 11.34 8.235 ;
     RECT  0.54 8.505 11.34 8.775 ;
     RECT  0.54 9.045 11.34 9.315 ;
     RECT  0.54 9.585 11.34 9.855 ;
     RECT  0.54 10.125 11.34 10.395 ;
     RECT  0.54 10.665 11.34 10.935 ;
     RECT  0.54 11.205 11.34 11.475 ;
     RECT  0.54 11.745 11.34 12.015 ;
     RECT  0.54 12.285 11.34 12.555 ;
     RECT  0.54 12.825 11.34 13.095 ;
     RECT  0.54 13.365 11.34 13.635 ;
     RECT  0.54 13.905 11.34 14.175 ;
     RECT  0.54 14.445 11.34 14.715 ;
     RECT  0.54 14.985 11.34 15.255 ;
     RECT  0.54 15.525 11.34 15.795 ;
     RECT  0.54 16.065 11.34 16.335 ;
     RECT  0.54 16.605 11.34 16.875 ;
     RECT  0.54 17.145 11.34 17.415 ;
     RECT  0.54 17.685 11.34 17.955 ;
     RECT  0.54 18.225 11.34 18.495 ;
     RECT  0.54 18.765 11.34 19.035 ;
     RECT  0.54 19.305 11.34 19.575 ;
     RECT  0.54 19.845 11.34 20.115 ;
     RECT  0.54 20.385 11.34 20.655 ;
     RECT  0.54 20.925 11.34 21.195 ;
     RECT  0.54 21.465 11.34 21.735 ;
     RECT  0.54 22.005 11.34 22.275 ;
     RECT  0.54 22.545 11.34 22.815 ;
     RECT  0.54 23.085 11.34 23.355 ;
     RECT  0.54 23.625 11.34 23.895 ;
     RECT  0.54 24.165 11.34 24.435 ;
     RECT  0.54 24.705 11.34 24.975 ;
     RECT  0.54 25.245 11.34 25.515 ;
     RECT  0.54 25.785 11.34 26.055 ;
     RECT  0.54 26.325 11.34 26.595 ;
     RECT  0.54 26.865 11.34 27.135 ;
     RECT  0.54 27.405 11.34 27.54 ;
    LAYER RVTP ;
     RECT  0.54 0.675 11.34 0.945 ;
     RECT  0.54 1.215 11.34 1.485 ;
     RECT  0.54 1.755 11.34 2.025 ;
     RECT  0.54 2.295 11.34 2.565 ;
     RECT  0.54 2.835 11.34 3.105 ;
     RECT  0.54 3.375 11.34 3.645 ;
     RECT  0.54 3.915 11.34 4.185 ;
     RECT  0.54 4.455 11.34 4.725 ;
     RECT  0.54 4.995 11.34 5.265 ;
     RECT  0.54 5.535 11.34 5.805 ;
     RECT  0.54 6.075 11.34 6.345 ;
     RECT  0.54 6.615 11.34 6.885 ;
     RECT  0.54 7.155 11.34 7.425 ;
     RECT  0.54 7.695 11.34 7.965 ;
     RECT  0.54 8.235 11.34 8.505 ;
     RECT  0.54 8.775 11.34 9.045 ;
     RECT  0.54 9.315 11.34 9.585 ;
     RECT  0.54 9.855 11.34 10.125 ;
     RECT  0.54 10.395 11.34 10.665 ;
     RECT  0.54 10.935 11.34 11.205 ;
     RECT  0.54 11.475 11.34 11.745 ;
     RECT  0.54 12.015 11.34 12.285 ;
     RECT  0.54 12.555 11.34 12.825 ;
     RECT  0.54 13.095 11.34 13.365 ;
     RECT  0.54 13.635 11.34 13.905 ;
     RECT  0.54 14.175 11.34 14.445 ;
     RECT  0.54 14.715 11.34 14.985 ;
     RECT  0.54 15.255 11.34 15.525 ;
     RECT  0.54 15.795 11.34 16.065 ;
     RECT  0.54 16.335 11.34 16.605 ;
     RECT  0.54 16.875 11.34 17.145 ;
     RECT  0.54 17.415 11.34 17.685 ;
     RECT  0.54 17.955 11.34 18.225 ;
     RECT  0.54 18.495 11.34 18.765 ;
     RECT  0.54 19.035 11.34 19.305 ;
     RECT  0.54 19.575 11.34 19.845 ;
     RECT  0.54 20.115 11.34 20.385 ;
     RECT  0.54 20.655 11.34 20.925 ;
     RECT  0.54 21.195 11.34 21.465 ;
     RECT  0.54 21.735 11.34 22.005 ;
     RECT  0.54 22.275 11.34 22.545 ;
     RECT  0.54 22.815 11.34 23.085 ;
     RECT  0.54 23.355 11.34 23.625 ;
     RECT  0.54 23.895 11.34 24.165 ;
     RECT  0.54 24.435 11.34 24.705 ;
     RECT  0.54 24.975 11.34 25.245 ;
     RECT  0.54 25.515 11.34 25.785 ;
     RECT  0.54 26.055 11.34 26.325 ;
     RECT  0.54 26.595 11.34 26.865 ;
     RECT  0.54 27.135 11.34 27.405 ;
    LAYER M1 ;
     RECT  0.54 0.531 11.34 27.549 ;
    LAYER M2 ;
     RECT  0.211 1.422 0.247 1.44 ;
     RECT  0.211 2.34 0.247 6.3 ;
     RECT  0.211 7.902 0.247 8.73 ;
     RECT  0.211 9.522 0.247 11.43 ;
     RECT  0.211 12.222 0.247 16.02 ;
     RECT  0.211 16.812 0.247 24.66 ;
     RECT  0.247 0.72 0.283 1.44 ;
     RECT  0.247 7.902 0.283 11.43 ;
     RECT  0.247 12.222 0.283 24.66 ;
     RECT  0.283 0.648 0.54 1.44 ;
     RECT  0.247 2.34 0.54 6.57 ;
     RECT  0.283 7.902 0.54 24.66 ;
     RECT  0.211 25.452 0.54 25.47 ;
     RECT  0.211 26.532 0.54 26.55 ;
     RECT  0.54 0.531 11.34 27.549 ;
     RECT  11.34 2.502 11.687 2.52 ;
     RECT  11.34 14.886 11.687 14.904 ;
    LAYER M3 ;
     RECT  0.684 0.379 0.702 0.523 ;
     RECT  0.684 0.523 0.885 0.571 ;
     RECT  10.836 0.379 10.854 0.571 ;
     RECT  0.216 0.571 0.885 0.643 ;
     RECT  1.728 0.571 2.322 0.643 ;
     RECT  0.216 0.643 3.006 0.679 ;
     RECT  0.216 0.679 3.438 0.715 ;
     RECT  10.836 0.571 10.89 0.763 ;
     RECT  6.195 0.523 6.285 0.793 ;
     RECT  10.836 0.763 11.214 0.841 ;
     RECT  10.044 0.841 10.062 0.877 ;
     RECT  10.8 0.841 11.214 0.877 ;
     RECT  5.076 0.715 5.094 0.949 ;
     RECT  10.044 0.877 11.214 0.949 ;
     RECT  9.324 0.949 11.214 0.977 ;
     RECT  0.216 0.715 3.51 0.985 ;
     RECT  8.568 0.715 8.586 0.985 ;
     RECT  0.216 0.985 3.654 1.099 ;
     RECT  5.076 0.949 5.31 1.111 ;
     RECT  8.496 0.985 8.586 1.139 ;
     RECT  10.548 0.977 11.214 1.139 ;
     RECT  0.216 1.099 4.266 1.175 ;
     RECT  9.324 0.977 9.522 1.181 ;
     RECT  5.04 1.111 5.382 1.211 ;
     RECT  3.888 1.175 4.266 1.219 ;
     RECT  6.195 0.793 6.477 1.291 ;
     RECT  7.308 0.751 7.326 1.291 ;
     RECT  8.568 1.139 8.586 1.291 ;
     RECT  9.324 1.181 9.414 1.291 ;
     RECT  8.568 1.291 9.414 1.319 ;
     RECT  6.195 1.291 7.326 1.381 ;
     RECT  3.888 1.219 4.41 1.409 ;
     RECT  10.692 1.139 11.214 1.409 ;
     RECT  0.216 1.175 3.15 1.445 ;
     RECT  10.692 1.409 10.998 1.445 ;
     RECT  5.94 1.381 7.326 1.679 ;
     RECT  9 1.319 9.414 1.709 ;
     RECT  0.288 1.445 3.15 1.921 ;
     RECT  3.888 1.409 4.266 1.921 ;
     RECT  5.94 1.679 7.038 2.059 ;
     RECT  9.396 1.709 9.414 2.191 ;
     RECT  5.544 2.059 7.038 2.219 ;
     RECT  0.288 1.921 4.266 2.299 ;
     RECT  5.544 2.219 6.477 2.299 ;
     RECT  10.692 1.445 10.926 2.299 ;
     RECT  0.216 2.299 4.266 2.371 ;
     RECT  10.692 2.299 11.214 2.371 ;
     RECT  0.216 2.371 4.554 2.489 ;
     RECT  5.508 2.299 6.477 2.489 ;
     RECT  10.656 2.371 11.214 2.491 ;
     RECT  10.656 2.491 11.682 2.525 ;
     RECT  9.396 2.191 9.486 2.641 ;
     RECT  9.396 2.641 9.558 2.683 ;
     RECT  9.396 2.683 9.666 2.765 ;
     RECT  5.58 2.489 6.477 2.795 ;
     RECT  10.656 2.525 11.214 2.795 ;
     RECT  8.568 2.875 8.586 3.001 ;
     RECT  8.568 3.001 8.838 3.029 ;
     RECT  10.836 2.795 11.214 3.029 ;
     RECT  0.216 2.489 4.374 3.065 ;
     RECT  9.684 3.001 9.882 3.065 ;
     RECT  9.864 3.065 9.882 3.067 ;
     RECT  6.156 2.795 6.477 3.101 ;
     RECT  8.82 3.029 8.838 3.101 ;
     RECT  9.864 3.067 9.99 3.101 ;
     RECT  10.836 3.029 10.998 3.101 ;
     RECT  4.356 3.065 4.374 3.137 ;
     RECT  9.972 3.101 9.99 3.173 ;
     RECT  6.195 3.101 6.477 3.541 ;
     RECT  6.195 3.541 6.894 3.641 ;
     RECT  10.836 3.101 10.854 3.643 ;
     RECT  5.04 3.451 5.058 3.685 ;
     RECT  5.04 3.685 5.166 3.721 ;
     RECT  10.8 3.643 10.854 3.811 ;
     RECT  5.04 3.721 5.346 3.931 ;
     RECT  0.216 3.065 3.546 3.955 ;
     RECT  4.536 3.931 5.346 4.027 ;
     RECT  6.195 3.641 6.477 4.027 ;
     RECT  10.368 3.811 10.854 4.081 ;
     RECT  7.524 3.991 7.542 4.109 ;
     RECT  0.216 3.955 3.618 4.261 ;
     RECT  4.536 4.027 6.477 4.261 ;
     RECT  8.676 4.075 8.694 4.261 ;
     RECT  0.216 4.261 6.477 4.379 ;
     RECT  10.044 4.081 10.854 4.411 ;
     RECT  8.676 4.261 8.838 4.445 ;
     RECT  9.612 4.411 10.854 4.451 ;
     RECT  6.084 4.379 6.477 4.559 ;
     RECT  10.26 4.451 10.854 4.621 ;
     RECT  8.352 4.621 8.514 4.685 ;
     RECT  8.352 4.685 8.37 4.699 ;
     RECT  10.26 4.621 10.998 4.795 ;
     RECT  10.26 4.795 11.214 4.829 ;
     RECT  7.704 4.699 8.37 4.919 ;
     RECT  7.992 4.919 8.37 4.955 ;
     RECT  10.26 4.829 10.854 4.955 ;
     RECT  10.476 4.955 10.854 5.021 ;
     RECT  0.216 4.379 5.31 5.117 ;
     RECT  4.932 5.117 5.31 5.131 ;
     RECT  10.8 5.021 10.854 5.405 ;
     RECT  0.216 5.117 4.197 5.496 ;
     RECT  0.216 5.496 4.194 5.501 ;
     RECT  7.992 4.955 8.01 5.701 ;
     RECT  10.836 5.405 10.854 5.755 ;
     RECT  10.836 5.755 11.214 5.801 ;
     RECT  4.932 5.131 5.382 5.971 ;
     RECT  7.992 5.701 8.802 5.971 ;
     RECT  9.792 5.881 9.81 5.999 ;
     RECT  6.195 4.559 6.477 6.043 ;
     RECT  7.452 5.971 8.802 6.043 ;
     RECT  4.932 5.971 5.418 6.071 ;
     RECT  10.836 5.801 11.142 6.139 ;
     RECT  6.195 6.043 8.802 6.151 ;
     RECT  5.94 6.151 8.802 6.269 ;
     RECT  0.216 5.501 3.726 6.305 ;
     RECT  10.26 6.139 11.142 6.557 ;
     RECT  0.252 6.305 3.726 6.575 ;
     RECT  8.568 6.269 8.802 6.619 ;
     RECT  4.932 6.071 5.202 6.667 ;
     RECT  0.684 6.575 3.726 6.691 ;
     RECT  10.26 6.557 10.962 6.749 ;
     RECT  8.568 6.619 9.054 6.781 ;
     RECT  6.195 6.269 7.722 6.809 ;
     RECT  10.296 6.749 10.962 6.809 ;
     RECT  0.684 6.691 3.798 6.811 ;
     RECT  4.644 6.667 5.202 6.811 ;
     RECT  6.195 6.809 6.534 6.845 ;
     RECT  10.296 6.809 10.854 6.941 ;
     RECT  8.568 6.781 9.126 6.953 ;
     RECT  0.684 6.811 5.202 7.133 ;
     RECT  5.112 7.133 5.202 7.231 ;
     RECT  6.195 6.845 6.477 7.231 ;
     RECT  0.684 7.133 4.338 7.421 ;
     RECT  10.332 6.941 10.854 7.421 ;
     RECT  8.568 6.953 8.946 7.435 ;
     RECT  8.46 7.435 8.946 7.469 ;
     RECT  5.112 7.231 6.477 7.655 ;
     RECT  0.684 7.421 3.978 7.675 ;
     RECT  10.548 7.421 10.854 7.709 ;
     RECT  8.46 7.469 8.622 7.735 ;
     RECT  5.256 7.655 6.477 7.771 ;
     RECT  8.172 7.735 8.622 7.861 ;
     RECT  5.256 7.771 6.858 7.889 ;
     RECT  7.956 7.861 8.622 7.901 ;
     RECT  9.504 7.735 9.522 7.901 ;
     RECT  7.956 7.901 8.478 7.961 ;
     RECT  5.256 7.889 6.822 7.997 ;
     RECT  10.728 7.709 10.854 8.059 ;
     RECT  5.256 7.997 6.477 8.159 ;
     RECT  10.728 8.059 10.926 8.195 ;
     RECT  10.836 8.195 10.926 8.239 ;
     RECT  10.836 8.239 11.214 8.285 ;
     RECT  0.216 7.675 3.978 8.311 ;
     RECT  0.216 8.311 4.158 8.401 ;
     RECT  8.28 7.961 8.478 8.477 ;
     RECT  9.648 8.437 9.666 8.477 ;
     RECT  8.28 8.477 8.298 8.501 ;
     RECT  9.792 8.671 9.81 8.771 ;
     RECT  0.216 8.401 5.094 9.005 ;
     RECT  6.195 8.159 6.477 9.115 ;
     RECT  10.836 8.285 10.89 9.211 ;
     RECT  0.216 9.005 4.41 9.275 ;
     RECT  5.904 9.115 6.477 9.355 ;
     RECT  8.244 9.481 8.262 9.581 ;
     RECT  10.188 9.211 10.89 9.595 ;
     RECT  10.188 9.595 10.926 9.661 ;
     RECT  9.648 9.661 10.926 9.689 ;
     RECT  7.92 9.661 8.082 9.751 ;
     RECT  5.292 9.355 6.477 9.787 ;
     RECT  5.292 9.787 6.714 9.821 ;
     RECT  4.068 9.275 4.41 9.883 ;
     RECT  4.068 9.883 5.13 9.965 ;
     RECT  9.648 9.689 10.854 10.013 ;
     RECT  4.068 9.965 4.626 10.049 ;
     RECT  9.648 10.013 9.666 10.049 ;
     RECT  10.404 10.013 10.854 10.085 ;
     RECT  0.216 9.275 3.078 10.165 ;
     RECT  4.068 10.049 4.122 10.165 ;
     RECT  10.584 10.085 10.854 10.435 ;
     RECT  6.156 9.821 6.714 10.471 ;
     RECT  6.156 10.471 6.966 10.589 ;
     RECT  7.776 9.751 8.082 10.597 ;
     RECT  0.216 10.165 4.122 10.625 ;
     RECT  7.485 10.597 8.082 10.705 ;
     RECT  9.216 10.651 9.234 10.705 ;
     RECT  7.485 10.705 9.234 10.769 ;
     RECT  10.584 10.435 10.926 10.831 ;
     RECT  10.584 10.831 10.962 10.903 ;
     RECT  3.348 10.625 4.122 10.939 ;
     RECT  10.152 10.903 10.962 10.939 ;
     RECT  3.348 10.939 4.194 10.941 ;
     RECT  3.348 10.941 4.197 11.011 ;
     RECT  7.485 10.769 8.73 11.039 ;
     RECT  10.152 10.939 11.142 11.039 ;
     RECT  6.156 10.589 6.477 11.179 ;
     RECT  3.348 11.011 4.518 11.281 ;
     RECT  7.956 11.039 8.73 11.399 ;
     RECT  8.028 11.399 8.586 11.405 ;
     RECT  8.568 11.405 8.586 11.435 ;
     RECT  10.152 11.039 10.962 11.471 ;
     RECT  0.216 10.625 2.502 11.515 ;
     RECT  3.348 11.281 4.698 11.515 ;
     RECT  5.58 11.179 6.477 11.551 ;
     RECT  5.58 11.551 7.11 11.669 ;
     RECT  5.58 11.669 6.966 11.705 ;
     RECT  9.792 11.641 9.81 11.741 ;
     RECT  10.836 11.471 10.962 11.741 ;
     RECT  0.216 11.515 4.698 11.785 ;
     RECT  5.58 11.705 6.786 11.785 ;
     RECT  9.684 11.911 9.702 12.011 ;
     RECT  0.216 11.785 6.786 12.119 ;
     RECT  0.216 12.119 4.554 12.209 ;
     RECT  0.216 12.209 4.194 12.317 ;
     RECT  0.216 12.317 2.862 12.389 ;
     RECT  10.836 11.741 10.89 12.475 ;
     RECT  10.8 12.475 10.89 12.515 ;
     RECT  5.4 12.119 6.786 12.551 ;
     RECT  5.508 12.551 6.786 12.721 ;
     RECT  5.508 12.721 7.038 12.821 ;
     RECT  10.836 12.515 10.89 13.051 ;
     RECT  3.744 12.317 4.194 13.099 ;
     RECT  7.992 13.099 8.01 13.171 ;
     RECT  7.848 13.171 8.01 13.261 ;
     RECT  3.744 13.099 4.518 13.339 ;
     RECT  5.508 12.821 6.477 13.339 ;
     RECT  7.632 13.261 8.154 13.361 ;
     RECT  10.836 13.051 10.926 13.369 ;
     RECT  7.74 13.361 8.154 13.373 ;
     RECT  0.216 12.389 2.754 13.405 ;
     RECT  10.836 13.369 10.998 13.405 ;
     RECT  0.216 13.405 2.826 13.441 ;
     RECT  3.744 13.339 6.477 13.441 ;
     RECT  10.692 13.405 10.998 13.531 ;
     RECT  7.74 13.373 7.974 13.559 ;
     RECT  10.44 13.531 10.998 13.627 ;
     RECT  10.44 13.627 11.214 13.631 ;
     RECT  7.956 13.559 7.974 13.709 ;
     RECT  10.656 13.631 11.214 13.853 ;
     RECT  0.216 13.441 6.477 13.865 ;
     RECT  8.892 13.675 8.91 14.143 ;
     RECT  8.892 14.143 9.054 14.251 ;
     RECT  8.892 14.251 9.45 14.285 ;
     RECT  9 14.285 9.45 14.341 ;
     RECT  4.968 13.865 6.477 14.347 ;
     RECT  9 14.341 9.594 14.369 ;
     RECT  9.432 14.369 9.594 14.405 ;
     RECT  10.836 13.853 11.214 14.441 ;
     RECT  4.968 14.347 6.57 14.549 ;
     RECT  10.836 14.441 10.854 14.639 ;
     RECT  0.216 13.865 3.978 14.791 ;
     RECT  4.968 14.549 6.477 14.791 ;
     RECT  0.216 14.791 6.477 14.909 ;
     RECT  11.664 14.779 11.682 14.909 ;
     RECT  9.648 14.881 9.666 15.005 ;
     RECT  3.132 14.909 6.477 15.089 ;
     RECT  3.132 15.089 4.374 15.101 ;
     RECT  8.028 14.881 8.046 15.151 ;
     RECT  8.028 15.151 8.118 15.187 ;
     RECT  3.132 15.101 4.014 15.215 ;
     RECT  10.224 15.151 10.242 15.421 ;
     RECT  11.016 15.355 11.034 15.421 ;
     RECT  10.224 15.421 11.034 15.449 ;
     RECT  5.508 15.089 6.477 15.457 ;
     RECT  7.848 15.187 8.118 15.601 ;
     RECT  10.224 15.449 10.854 15.629 ;
     RECT  0.216 14.909 2.286 15.691 ;
     RECT  3.132 15.215 3.762 15.691 ;
     RECT  7.848 15.601 8.514 15.755 ;
     RECT  10.224 15.629 10.674 15.799 ;
     RECT  0.216 15.691 3.762 15.827 ;
     RECT  9.828 15.799 10.674 15.899 ;
     RECT  9.9 15.899 10.674 15.917 ;
     RECT  7.848 15.755 7.974 15.961 ;
     RECT  5.508 15.457 6.858 15.989 ;
     RECT  3.204 15.827 3.762 16.013 ;
     RECT  3.348 16.013 3.762 16.025 ;
     RECT  7.812 15.961 7.974 16.123 ;
     RECT  6.048 15.989 6.858 16.141 ;
     RECT  7.668 16.123 7.974 16.141 ;
     RECT  4.32 16.105 4.338 16.267 ;
     RECT  8.712 16.231 8.73 16.331 ;
     RECT  10.224 15.917 10.674 16.375 ;
     RECT  6.048 16.141 7.974 16.403 ;
     RECT  6.048 16.403 6.858 16.439 ;
     RECT  7.956 16.403 7.974 16.537 ;
     RECT  7.956 16.537 8.406 16.565 ;
     RECT  6.048 16.439 6.717 16.771 ;
     RECT  10.224 16.375 10.854 16.771 ;
     RECT  4.32 16.267 4.986 16.843 ;
     RECT  5.904 16.771 6.717 16.843 ;
     RECT  0.216 15.827 2.394 16.951 ;
     RECT  9.54 16.771 10.854 16.951 ;
     RECT  0.216 16.951 2.574 17.035 ;
     RECT  9.18 16.951 10.854 17.041 ;
     RECT  9.18 17.041 10.926 17.069 ;
     RECT  0.216 17.035 2.61 17.083 ;
     RECT  3.528 16.025 3.546 17.083 ;
     RECT  4.32 16.843 6.717 17.117 ;
     RECT  0.216 17.083 3.546 17.221 ;
     RECT  9.18 17.069 9.558 17.339 ;
     RECT  9.36 17.339 9.378 17.375 ;
     RECT  8.244 16.565 8.406 17.419 ;
     RECT  10.332 17.069 10.926 17.455 ;
     RECT  10.332 17.455 11.106 17.501 ;
     RECT  4.824 17.117 6.717 17.581 ;
     RECT  8.244 17.419 8.586 17.609 ;
     RECT  8.244 17.609 8.334 17.611 ;
     RECT  4.824 17.581 6.822 17.645 ;
     RECT  10.332 17.501 10.926 17.681 ;
     RECT  10.548 17.681 10.926 17.693 ;
     RECT  6.195 17.645 6.822 17.761 ;
     RECT  7.848 17.611 8.334 17.879 ;
     RECT  4.824 17.645 5.346 17.915 ;
     RECT  6.195 17.761 6.894 17.959 ;
     RECT  7.848 17.879 7.938 17.959 ;
     RECT  6.195 17.959 7.938 18.029 ;
     RECT  0.216 17.221 3.978 18.121 ;
     RECT  5.148 17.915 5.346 18.173 ;
     RECT  6.195 18.029 7.434 18.173 ;
     RECT  0.216 18.121 4.014 18.221 ;
     RECT  5.148 18.173 5.202 18.221 ;
     RECT  10.764 17.693 10.926 18.269 ;
     RECT  10.764 18.269 10.854 18.571 ;
     RECT  8.316 18.661 8.334 18.725 ;
     RECT  7.344 18.173 7.434 18.769 ;
     RECT  6.195 18.173 6.477 18.811 ;
     RECT  10.26 18.571 10.854 18.845 ;
     RECT  4.752 18.841 4.77 18.959 ;
     RECT  7.344 18.769 7.902 18.959 ;
     RECT  0.216 18.221 3.942 19.237 ;
     RECT  6.048 18.811 6.477 19.273 ;
     RECT  7.344 18.959 7.542 19.273 ;
     RECT  6.048 19.273 7.542 19.373 ;
     RECT  9.648 19.195 9.666 19.387 ;
     RECT  7.308 19.373 7.542 19.571 ;
     RECT  10.836 18.845 10.854 19.579 ;
     RECT  6.048 19.373 6.477 19.651 ;
     RECT  5.652 19.651 6.477 19.805 ;
     RECT  0.216 19.237 3.978 19.885 ;
     RECT  9.432 19.387 9.666 19.921 ;
     RECT  10.836 19.579 11.214 19.921 ;
     RECT  7.776 19.777 7.794 19.949 ;
     RECT  9.288 19.921 11.214 20.189 ;
     RECT  8.352 20.155 8.37 20.191 ;
     RECT  9.288 20.189 10.674 20.381 ;
     RECT  0.216 19.885 4.482 20.453 ;
     RECT  8.352 20.191 8.514 20.491 ;
     RECT  9.288 20.381 10.35 20.491 ;
     RECT  4.32 20.453 4.482 20.539 ;
     RECT  6.195 19.805 6.477 20.539 ;
     RECT  6.048 20.539 6.477 20.551 ;
     RECT  8.352 20.491 10.35 20.579 ;
     RECT  6.048 20.551 7.578 20.651 ;
     RECT  4.32 20.539 4.842 20.731 ;
     RECT  4.32 20.731 5.022 20.821 ;
     RECT  6.048 20.651 6.57 20.821 ;
     RECT  7.308 20.651 7.578 20.849 ;
     RECT  4.32 20.821 6.57 20.861 ;
     RECT  7.38 20.849 7.578 20.929 ;
     RECT  8.352 20.579 10.278 20.929 ;
     RECT  4.32 20.861 6.477 20.993 ;
     RECT  7.38 20.929 10.278 21.119 ;
     RECT  0.216 20.453 3.546 21.199 ;
     RECT  4.32 20.993 5.058 21.199 ;
     RECT  8.82 21.119 10.278 21.227 ;
     RECT  8.82 21.227 9.882 21.425 ;
     RECT  10.836 21.307 10.854 21.469 ;
     RECT  10.836 21.469 10.89 21.499 ;
     RECT  10.836 21.499 11.214 21.533 ;
     RECT  6.12 20.993 6.477 21.643 ;
     RECT  7.38 21.119 8.046 21.643 ;
     RECT  0.216 21.199 5.058 21.659 ;
     RECT  8.82 21.425 9.162 21.659 ;
     RECT  10.836 21.533 10.998 21.659 ;
     RECT  8.82 21.659 9.09 21.677 ;
     RECT  6.12 21.643 8.046 21.901 ;
     RECT  0.216 21.659 4.518 21.929 ;
     RECT  4.176 21.929 4.482 21.965 ;
     RECT  5.94 21.901 8.406 22.045 ;
     RECT  10.836 21.659 10.89 22.075 ;
     RECT  10.224 22.075 10.89 22.109 ;
     RECT  0.216 21.929 3.438 22.199 ;
     RECT  5.76 22.045 8.406 22.235 ;
     RECT  10.8 22.109 10.89 22.301 ;
     RECT  9.612 22.459 9.63 22.505 ;
     RECT  7.488 22.235 8.406 22.541 ;
     RECT  5.76 22.235 6.678 22.585 ;
     RECT  10.836 22.301 10.89 22.621 ;
     RECT  8.856 22.711 8.874 22.811 ;
     RECT  10.836 22.621 10.926 23.069 ;
     RECT  4.248 21.965 4.482 23.125 ;
     RECT  3.996 23.125 4.734 23.161 ;
     RECT  5.688 22.585 6.678 23.161 ;
     RECT  7.488 22.541 7.938 23.161 ;
     RECT  10.836 23.069 10.89 23.251 ;
     RECT  10.224 23.251 10.89 23.261 ;
     RECT  5.688 23.161 7.938 23.275 ;
     RECT  5.472 23.275 7.938 23.279 ;
     RECT  7.668 23.279 7.938 23.287 ;
     RECT  3.852 23.161 4.734 23.323 ;
     RECT  5.472 23.279 6.894 23.323 ;
     RECT  7.668 23.287 8.118 23.387 ;
     RECT  0.216 22.199 2.97 23.431 ;
     RECT  0.216 23.431 3.078 23.521 ;
     RECT  3.852 23.323 6.894 23.521 ;
     RECT  0.216 23.521 6.894 23.657 ;
     RECT  9.144 22.891 9.378 23.701 ;
     RECT  9.108 23.701 9.378 23.791 ;
     RECT  10.224 23.261 10.854 23.791 ;
     RECT  7.668 23.387 7.974 23.819 ;
     RECT  9.108 23.791 10.854 23.891 ;
     RECT  9.108 23.891 9.306 23.927 ;
     RECT  10.476 23.891 10.854 24.029 ;
     RECT  9.108 23.927 9.234 24.043 ;
     RECT  7.812 23.819 7.974 24.077 ;
     RECT  8.964 24.043 9.234 24.089 ;
     RECT  10.836 24.029 10.854 24.187 ;
     RECT  9.108 24.089 9.234 24.359 ;
     RECT  5.544 23.657 6.894 24.511 ;
     RECT  8.28 24.511 8.298 24.629 ;
     RECT  9.216 24.359 9.234 24.665 ;
     RECT  0.216 23.657 4.662 24.709 ;
     RECT  5.544 24.511 6.93 24.709 ;
     RECT  10.836 24.187 11.106 24.763 ;
     RECT  10.836 24.763 11.214 24.809 ;
     RECT  0.216 24.709 6.93 24.899 ;
     RECT  9.36 24.745 9.378 24.899 ;
     RECT  10.836 24.809 10.854 25.141 ;
     RECT  5.688 24.899 6.93 25.205 ;
     RECT  5.976 25.205 6.93 25.313 ;
     RECT  10.44 25.141 10.854 25.411 ;
     RECT  0.216 24.899 4.914 25.439 ;
     RECT  9.792 25.411 10.854 25.531 ;
     RECT  3.276 25.439 4.914 25.709 ;
     RECT  5.976 25.313 6.858 25.709 ;
     RECT  4.536 25.709 4.914 25.745 ;
     RECT  6.156 25.709 6.858 25.757 ;
     RECT  0.216 25.439 2.394 25.781 ;
     RECT  7.812 25.147 7.83 25.825 ;
     RECT  7.812 25.825 8.01 25.861 ;
     RECT  9.792 25.531 10.926 25.949 ;
     RECT  9 25.825 9.018 25.963 ;
     RECT  0.216 25.781 1.89 25.979 ;
     RECT  7.704 25.861 8.01 25.979 ;
     RECT  8.82 25.963 9.018 25.979 ;
     RECT  9.792 25.949 10.35 25.979 ;
     RECT  7.812 25.979 8.01 25.997 ;
     RECT  4.536 25.745 4.806 26.015 ;
     RECT  8.82 25.979 8.838 26.015 ;
     RECT  10.116 25.979 10.35 26.015 ;
     RECT  11.088 26.095 11.106 26.141 ;
     RECT  0.216 25.979 1.854 26.249 ;
     RECT  4.536 26.015 4.698 26.249 ;
     RECT  7.92 25.997 8.01 26.249 ;
     RECT  3.276 25.709 3.618 26.285 ;
     RECT  10.332 26.015 10.35 26.333 ;
     RECT  2.952 26.365 2.97 26.429 ;
     RECT  4.608 26.249 4.698 26.429 ;
     RECT  7.92 26.249 7.938 26.429 ;
     RECT  4.68 26.429 4.698 26.519 ;
     RECT  0.216 26.249 1.674 26.555 ;
     RECT  0.576 26.555 1.35 26.789 ;
     RECT  0.576 26.789 1.314 26.825 ;
     RECT  0.684 26.825 1.314 27.059 ;
     RECT  0.684 27.059 1.242 27.095 ;
     RECT  0.795 27.095 1.077 27.287 ;
     RECT  6.195 25.757 6.477 27.287 ;
     RECT  0.795 27.287 0.954 27.365 ;
     RECT  0.795 27.365 0.885 27.557 ;
     RECT  6.195 27.287 6.285 27.557 ;
    LAYER M4 ;
     RECT  0.156 0.384 0.565 26.328 ;
     RECT  0.565 0.384 0.713 26.856 ;
     RECT  0.713 0.528 0.788 26.856 ;
     RECT  0.788 0.528 0.892 27.552 ;
     RECT  0.892 0.672 1.084 27.282 ;
     RECT  1.084 24.384 1.145 27.096 ;
     RECT  1.084 17.664 1.235 23.4 ;
     RECT  1.145 24.432 1.235 27.096 ;
     RECT  1.084 0.672 1.253 2.952 ;
     RECT  1.235 20.64 1.253 20.664 ;
     RECT  1.235 21.984 1.253 22.872 ;
     RECT  1.235 24.432 1.253 26.856 ;
     RECT  1.253 26.256 1.379 26.856 ;
     RECT  1.379 26.256 1.397 26.28 ;
     RECT  1.235 17.664 1.577 19.464 ;
     RECT  1.084 5.088 1.667 5.256 ;
     RECT  1.577 19.392 1.721 19.464 ;
     RECT  1.253 0.912 1.793 2.952 ;
     RECT  1.253 21.984 1.811 22.68 ;
     RECT  1.084 15.312 1.829 15.96 ;
     RECT  1.084 9.792 1.865 14.28 ;
     RECT  1.577 17.664 1.865 18.408 ;
     RECT  1.811 22.656 1.907 22.68 ;
     RECT  1.829 15.936 2.009 15.96 ;
     RECT  1.793 0.912 2.045 1.704 ;
     RECT  1.253 24.432 2.045 25.128 ;
     RECT  1.865 14.208 2.051 14.28 ;
     RECT  1.084 6.864 2.099 8.04 ;
     RECT  2.099 6.864 2.113 7.992 ;
     RECT  1.865 9.792 2.113 12.936 ;
     RECT  1.865 17.664 2.117 18.264 ;
     RECT  2.045 24.432 2.117 24.504 ;
     RECT  2.117 17.664 2.149 18.216 ;
     RECT  2.113 6.192 2.195 7.992 ;
     RECT  2.113 9.648 2.195 12.936 ;
     RECT  1.667 5.088 2.221 5.208 ;
     RECT  2.195 9.792 2.225 12.936 ;
     RECT  2.221 4.56 2.243 5.208 ;
     RECT  2.225 9.792 2.261 12.552 ;
     RECT  2.293 23.952 2.339 24.12 ;
     RECT  2.149 17.616 2.365 18.216 ;
     RECT  2.365 17.088 2.389 18.216 ;
     RECT  1.793 2.688 2.437 2.952 ;
     RECT  2.339 23.952 2.441 23.976 ;
     RECT  2.293 22.896 2.485 22.92 ;
     RECT  2.437 2.688 2.513 3.24 ;
     RECT  2.261 9.792 2.531 12.456 ;
     RECT  2.051 14.256 2.533 14.28 ;
     RECT  2.485 22.896 2.549 23.352 ;
     RECT  2.389 17.04 2.621 18.216 ;
     RECT  2.243 4.56 2.677 5.112 ;
     RECT  1.721 19.392 2.693 19.416 ;
     RECT  2.677 3.744 2.729 5.112 ;
     RECT  2.549 22.896 2.801 22.92 ;
     RECT  2.513 2.688 2.867 2.76 ;
     RECT  2.045 1.104 2.869 1.704 ;
     RECT  2.729 4.272 2.945 5.112 ;
     RECT  2.533 14.256 2.945 14.52 ;
     RECT  2.869 22.8 2.945 22.824 ;
     RECT  2.531 9.792 2.981 11.832 ;
     RECT  2.917 26.4 2.981 26.424 ;
     RECT  2.621 17.088 3.059 18.216 ;
     RECT  3.059 17.088 3.125 17.112 ;
     RECT  2.869 1.104 3.197 2.328 ;
     RECT  2.257 15.984 3.253 16.008 ;
     RECT  2.195 6.24 3.265 7.992 ;
     RECT  3.197 2.304 3.305 2.328 ;
     RECT  3.265 5.616 3.305 7.992 ;
     RECT  2.833 19.632 3.373 20.328 ;
     RECT  3.059 18.144 3.397 18.216 ;
     RECT  3.253 14.784 3.443 16.008 ;
     RECT  3.305 7.44 3.521 7.992 ;
     RECT  2.981 9.792 3.625 10.92 ;
     RECT  3.373 19.632 3.665 20.568 ;
     RECT  3.397 18.144 3.805 18.312 ;
     RECT  3.625 9.12 3.973 10.92 ;
     RECT  3.805 11.952 3.973 11.976 ;
     RECT  3.841 13.008 3.973 13.032 ;
     RECT  3.973 9.12 4.019 11.976 ;
     RECT  3.805 18.144 4.019 18.84 ;
     RECT  2.945 4.272 4.021 4.536 ;
     RECT  3.521 7.968 4.021 7.992 ;
     RECT  4.019 9.12 4.021 11.784 ;
     RECT  4.021 7.968 4.067 11.784 ;
     RECT  4.067 8.736 4.133 11.784 ;
     RECT  4.021 3.936 4.165 4.536 ;
     RECT  3.305 5.616 4.165 6.264 ;
     RECT  2.401 21.648 4.165 21.672 ;
     RECT  4.129 25.056 4.165 25.08 ;
     RECT  4.165 21.648 4.205 21.768 ;
     RECT  4.165 25.056 4.211 25.704 ;
     RECT  4.021 2.832 4.277 2.856 ;
     RECT  4.165 3.936 4.309 6.264 ;
     RECT  3.125 17.091 4.357 17.109 ;
     RECT  4.357 16.56 4.381 17.109 ;
     RECT  3.443 14.784 4.403 15.384 ;
     RECT  3.665 19.92 4.499 20.568 ;
     RECT  4.309 3.936 4.525 6.84 ;
     RECT  4.499 20.016 4.547 20.568 ;
     RECT  4.381 16.56 4.549 17.112 ;
     RECT  4.019 18.144 4.549 18.216 ;
     RECT  4.549 16.56 4.813 18.216 ;
     RECT  4.211 25.68 4.817 25.704 ;
     RECT  4.547 20.544 4.853 20.568 ;
     RECT  4.403 15.024 4.921 15.384 ;
     RECT  4.813 16.368 4.921 18.216 ;
     RECT  3.973 13.008 4.957 13.128 ;
     RECT  4.133 8.736 5.029 9.96 ;
     RECT  3.197 1.104 5.105 1.128 ;
     RECT  4.525 3.936 5.177 7.128 ;
     RECT  4.957 13.008 5.461 13.416 ;
     RECT  4.921 15.024 5.461 18.216 ;
     RECT  4.133 10.944 5.497 11.784 ;
     RECT  5.461 13.008 5.497 18.216 ;
     RECT  5.177 4.032 5.605 7.128 ;
     RECT  5.029 8.448 5.605 9.96 ;
     RECT  5.461 23.28 5.857 23.304 ;
     RECT  5.605 4.032 6.037 9.96 ;
     RECT  5.497 10.944 6.037 18.216 ;
     RECT  5.821 19.776 6.037 19.8 ;
     RECT  6.037 4.032 6.145 20.568 ;
     RECT  5.533 1.68 6.188 2.088 ;
     RECT  6.145 3.072 6.188 20.568 ;
     RECT  4.205 21.747 6.188 21.765 ;
     RECT  5.857 23.136 6.188 23.304 ;
     RECT  6.145 24.624 6.188 24.648 ;
     RECT  6.145 25.728 6.188 25.752 ;
     RECT  6.188 0.528 6.292 27.552 ;
     RECT  6.292 0.798 6.484 27.282 ;
     RECT  6.484 1.248 6.611 4.728 ;
     RECT  6.484 9.552 6.689 11.784 ;
     RECT  6.484 15.696 6.761 18.168 ;
     RECT  6.484 19.776 6.851 24.648 ;
     RECT  6.851 19.776 6.941 24.072 ;
     RECT  6.941 22.752 7.589 24.072 ;
     RECT  6.484 25.728 7.801 25.752 ;
     RECT  6.761 15.696 7.837 17.637 ;
     RECT  7.837 15.696 7.841 17.64 ;
     RECT  7.801 25.152 7.859 25.992 ;
     RECT  7.841 16.848 7.909 17.64 ;
     RECT  7.909 16.848 7.955 18.024 ;
     RECT  6.484 13.344 7.981 14.376 ;
     RECT  6.611 4.416 8.021 4.728 ;
     RECT  6.689 9.552 8.051 11.688 ;
     RECT  7.981 13.104 8.051 14.376 ;
     RECT  8.051 9.552 8.057 11.4 ;
     RECT  8.051 13.344 8.165 14.376 ;
     RECT  8.057 9.552 8.273 11.256 ;
     RECT  7.841 15.696 8.387 15.72 ;
     RECT  7.955 16.848 8.417 17.496 ;
     RECT  6.484 5.856 8.489 8.472 ;
     RECT  8.021 4.416 8.525 4.68 ;
     RECT  8.417 17.184 8.597 17.496 ;
     RECT  8.489 5.856 8.629 7.896 ;
     RECT  8.525 4.416 8.665 4.44 ;
     RECT  8.629 5.712 8.669 7.896 ;
     RECT  8.665 4.08 8.723 4.44 ;
     RECT  8.669 5.712 8.723 5.88 ;
     RECT  8.273 9.888 8.741 11.256 ;
     RECT  8.723 5.856 8.813 5.88 ;
     RECT  7.859 25.968 8.849 25.992 ;
     RECT  8.165 13.68 8.921 14.376 ;
     RECT  6.611 1.68 8.989 3.096 ;
     RECT  8.921 14.16 9.065 14.376 ;
     RECT  6.941 19.776 9.109 21.672 ;
     RECT  7.589 23.28 9.205 24.072 ;
     RECT  8.741 9.888 9.245 10.68 ;
     RECT  9.109 19.392 9.245 21.672 ;
     RECT  9.245 21.648 9.251 21.672 ;
     RECT  9.205 22.992 9.251 24.648 ;
     RECT  8.597 17.184 9.389 17.304 ;
     RECT  8.989 1.584 9.425 3.096 ;
     RECT  9.065 14.256 9.461 14.376 ;
     RECT  9.425 2.208 9.497 3.096 ;
     RECT  9.389 17.184 9.569 17.208 ;
     RECT  9.251 22.992 9.601 23.304 ;
     RECT  9.461 14.352 9.605 14.376 ;
     RECT  9.245 19.392 9.605 20.568 ;
     RECT  8.669 7.104 9.637 7.896 ;
     RECT  9.637 14.976 9.877 15 ;
     RECT  9.637 7.104 10.213 8.472 ;
     RECT  9.245 9.888 10.213 9.912 ;
     RECT  9.877 14.976 10.213 15.912 ;
     RECT  9.601 22.464 10.213 23.304 ;
     RECT  8.723 4.416 10.249 4.44 ;
     RECT  10.213 7.104 10.249 10.008 ;
     RECT  9.637 19.2 10.249 19.224 ;
     RECT  9.605 20.544 10.249 20.568 ;
     RECT  10.213 22.08 10.249 23.448 ;
     RECT  9.497 2.688 10.357 3.096 ;
     RECT  10.249 4.416 10.357 4.632 ;
     RECT  10.249 6.72 10.357 10.008 ;
     RECT  10.321 26.304 10.357 26.328 ;
     RECT  10.357 2.688 10.465 4.632 ;
     RECT  10.249 20.544 10.465 23.448 ;
     RECT  10.213 14.976 10.537 16.92 ;
     RECT  10.249 18.624 10.537 19.224 ;
     RECT  10.357 6.144 10.573 10.008 ;
     RECT  10.465 20.544 10.645 24.024 ;
     RECT  10.357 25.92 10.645 26.328 ;
     RECT  9.493 1.152 10.681 1.176 ;
     RECT  10.465 2.688 10.681 5.016 ;
     RECT  10.645 13.824 10.681 13.848 ;
     RECT  10.681 1.152 10.789 5.016 ;
     RECT  10.573 6.144 10.789 10.2 ;
     RECT  10.681 13.44 10.789 13.848 ;
     RECT  10.789 0.96 10.825 10.2 ;
     RECT  10.789 12.48 10.825 13.848 ;
     RECT  10.537 14.976 10.825 19.224 ;
     RECT  10.645 20.352 10.825 24.024 ;
     RECT  10.645 25.344 10.825 26.328 ;
     RECT  10.825 0.384 11.724 26.328 ;
    LAYER M5 ;
     RECT  5.904 0.144 5.928 0.517 ;
     RECT  0.78 0.517 0.9 0.531 ;
     RECT  5.904 0.517 6.3 0.531 ;
     RECT  5.904 0.531 6.492 1.237 ;
     RECT  0.78 0.531 1.092 2.101 ;
     RECT  0.192 2.101 1.752 2.155 ;
     RECT  2.88 1.957 2.904 2.339 ;
     RECT  9.408 2.677 9.432 2.741 ;
     RECT  2.832 2.725 2.856 2.795 ;
     RECT  8.544 2.741 9.432 2.915 ;
     RECT  0.78 2.155 1.752 2.963 ;
     RECT  8.688 2.915 9.432 3.059 ;
     RECT  2.448 3.205 2.712 3.307 ;
     RECT  0.78 2.963 1.092 3.685 ;
     RECT  0.672 3.685 1.092 3.755 ;
     RECT  4.032 2.821 4.056 3.971 ;
     RECT  2.688 3.307 2.712 4.261 ;
     RECT  2.688 4.261 3.72 4.331 ;
     RECT  2.688 4.331 3.48 4.533 ;
     RECT  2.256 4.533 3.48 4.587 ;
     RECT  5.904 1.237 6.6 4.645 ;
     RECT  5.664 4.645 6.6 4.739 ;
     RECT  0.78 3.755 1.092 5.109 ;
     RECT  2.256 4.587 2.712 5.109 ;
     RECT  5.664 4.739 6.492 5.109 ;
     RECT  0.78 5.109 2.712 5.123 ;
     RECT  0.78 5.123 2.232 5.219 ;
     RECT  5.136 5.109 6.492 5.219 ;
     RECT  0.78 5.219 1.656 5.267 ;
     RECT  4.176 5.461 4.584 5.605 ;
     RECT  3.408 5.605 4.584 5.675 ;
     RECT  4.176 5.675 4.584 5.747 ;
     RECT  8.688 3.059 8.712 5.747 ;
     RECT  2.16 6.181 2.184 6.229 ;
     RECT  0.78 5.267 1.092 6.661 ;
     RECT  0.672 6.661 1.092 6.709 ;
     RECT  2.16 6.229 3.096 6.709 ;
     RECT  0.192 6.709 3.096 7.189 ;
     RECT  4.176 5.747 4.2 7.189 ;
     RECT  0.192 7.189 4.2 7.531 ;
     RECT  0.78 7.531 4.2 7.659 ;
     RECT  0.78 7.659 2.904 8.003 ;
     RECT  0.78 8.003 2.088 8.051 ;
     RECT  0.78 8.051 1.092 8.565 ;
     RECT  0.576 8.565 1.092 8.771 ;
     RECT  4.032 7.659 4.2 9.251 ;
     RECT  2.16 9.637 2.184 9.707 ;
     RECT  4.176 9.251 4.2 9.925 ;
     RECT  5.904 5.219 6.492 9.925 ;
     RECT  4.176 9.925 6.492 10.027 ;
     RECT  2.88 10.165 2.904 10.219 ;
     RECT  5.904 10.027 6.492 10.645 ;
     RECT  2.256 10.741 2.28 10.795 ;
     RECT  4.176 10.027 4.2 10.805 ;
     RECT  7.968 10.165 7.992 10.835 ;
     RECT  3.936 10.805 4.2 10.869 ;
     RECT  3.408 10.869 4.2 10.931 ;
     RECT  3.984 10.931 4.2 10.979 ;
     RECT  5.904 10.645 6.84 11.459 ;
     RECT  5.904 11.459 6.492 11.941 ;
     RECT  2.496 12.405 2.52 12.467 ;
     RECT  5.712 11.941 6.492 12.755 ;
     RECT  3.984 10.979 4.008 13.139 ;
     RECT  8.016 11.365 8.04 13.139 ;
     RECT  5.76 12.755 6.492 13.667 ;
     RECT  0.78 8.771 1.092 14.197 ;
     RECT  0.78 14.197 2.04 14.251 ;
     RECT  2.544 14.485 2.568 14.571 ;
     RECT  3.264 15.093 3.288 15.203 ;
     RECT  0.78 14.251 1.092 15.413 ;
     RECT  0.78 15.413 1.656 15.925 ;
     RECT  0.78 15.925 1.752 15.973 ;
     RECT  4.368 14.773 4.392 15.973 ;
     RECT  3.408 15.973 4.392 16.043 ;
     RECT  9.888 15.877 9.912 16.043 ;
     RECT  0.78 15.973 2.328 16.245 ;
     RECT  0.192 16.245 2.328 16.299 ;
     RECT  0.192 16.299 1.092 16.355 ;
     RECT  4.368 16.043 4.392 16.595 ;
     RECT  2.4 16.885 2.424 17.013 ;
     RECT  5.763 13.667 6.492 17.077 ;
     RECT  8.352 14.245 8.376 17.269 ;
     RECT  8.352 17.269 9.144 17.315 ;
     RECT  2.4 17.013 2.568 17.317 ;
     RECT  2.4 17.317 3.048 17.387 ;
     RECT  4.56 17.333 4.584 17.589 ;
     RECT  5.76 17.077 6.492 17.589 ;
     RECT  2.16 17.589 2.184 17.651 ;
     RECT  4.56 17.589 6.492 17.651 ;
     RECT  4.56 17.651 4.584 17.699 ;
     RECT  7.92 17.989 7.944 18.035 ;
     RECT  0.78 16.355 1.092 18.133 ;
     RECT  0.78 18.133 1.752 18.229 ;
     RECT  0.192 18.229 1.752 18.283 ;
     RECT  3.408 18.181 4.008 18.323 ;
     RECT  3.984 18.323 4.008 18.851 ;
     RECT  6.048 17.651 6.492 18.851 ;
     RECT  0.672 18.283 1.56 19.091 ;
     RECT  0.78 19.091 1.56 19.381 ;
     RECT  9.12 17.315 9.144 19.427 ;
     RECT  0.78 19.381 1.704 19.475 ;
     RECT  3.6 19.621 3.624 19.909 ;
     RECT  3.6 19.909 4.488 20.005 ;
     RECT  3.6 20.005 4.536 20.075 ;
     RECT  6.18 18.851 6.492 20.101 ;
     RECT  3.6 20.075 4.488 20.277 ;
     RECT  2.88 20.277 4.488 20.339 ;
     RECT  3.6 20.339 4.488 20.579 ;
     RECT  6.048 20.101 6.492 20.579 ;
     RECT  10.848 20.021 10.872 20.963 ;
     RECT  7.923 18.035 7.941 21.637 ;
     RECT  7.92 21.637 7.944 21.683 ;
     RECT  6.18 20.579 6.492 22.069 ;
     RECT  0.78 19.475 1.224 22.117 ;
     RECT  0.78 22.117 1.8 22.645 ;
     RECT  0.78 22.645 1.896 22.699 ;
     RECT  2.88 22.645 2.904 22.835 ;
     RECT  2.304 22.837 2.52 22.931 ;
     RECT  2.496 22.931 2.52 23.403 ;
     RECT  0.78 22.699 1.224 23.411 ;
     RECT  0.78 23.411 1.092 23.413 ;
     RECT  0.192 23.413 1.092 23.467 ;
     RECT  2.304 23.925 2.328 24.131 ;
     RECT  0.78 23.467 1.092 24.421 ;
     RECT  0.78 24.421 1.848 24.563 ;
     RECT  6.18 22.069 6.84 24.659 ;
     RECT  9.216 21.637 9.24 24.659 ;
     RECT  0.78 24.563 1.752 24.757 ;
     RECT  0.192 24.757 1.752 25.139 ;
     RECT  7.824 24.037 7.848 25.187 ;
     RECT  0.192 25.139 1.224 25.579 ;
     RECT  4.176 25.045 4.2 25.715 ;
     RECT  0.78 25.579 1.224 26.805 ;
     RECT  0.576 26.805 1.368 26.867 ;
     RECT  0.78 26.867 1.224 27.115 ;
     RECT  2.928 26.389 2.952 27.115 ;
     RECT  0.78 27.115 1.092 27.549 ;
     RECT  6.18 24.659 6.492 27.549 ;
     RECT  0.78 27.549 0.9 27.563 ;
     RECT  6.18 27.549 6.3 27.563 ;
    LAYER M6 ;
     RECT  0.181 6.72 0.309 8.032 ;
     RECT  0.181 24.768 0.437 26.4 ;
     RECT  0.309 6.72 0.611 8.608 ;
     RECT  0.181 18.24 0.661 18.272 ;
     RECT  0.661 3.712 0.747 3.744 ;
     RECT  0.181 16.256 0.949 16.288 ;
     RECT  1.077 21.12 1.141 21.152 ;
     RECT  0.181 23.424 1.141 23.456 ;
     RECT  0.437 24.768 1.141 26.848 ;
     RECT  0.661 18.24 1.189 19.04 ;
     RECT  1.141 21.12 1.189 21.728 ;
     RECT  1.141 23.424 1.189 26.848 ;
     RECT  1.189 18.24 1.235 21.728 ;
     RECT  1.189 23.36 1.235 27.104 ;
     RECT  1.235 26.816 1.387 27.104 ;
     RECT  1.235 23.36 1.429 25.12 ;
     RECT  0.181 2.112 1.621 2.144 ;
     RECT  0.693 5.12 1.621 5.152 ;
     RECT  0.949 16.256 1.621 16.928 ;
     RECT  1.621 2.112 1.653 2.912 ;
     RECT  1.621 5.12 1.653 5.216 ;
     RECT  1.621 15.424 1.653 16.928 ;
     RECT  1.235 18.24 1.653 20.32 ;
     RECT  1.653 14.528 1.715 20.32 ;
     RECT  1.429 22.208 1.763 25.12 ;
     RECT  1.763 22.208 1.835 24.544 ;
     RECT  1.835 22.656 1.899 24.544 ;
     RECT  1.715 14.528 2.005 18.272 ;
     RECT  0.611 6.72 2.037 8.032 ;
     RECT  2.037 6.656 2.099 8.032 ;
     RECT  1.653 4.288 2.149 5.216 ;
     RECT  2.099 6.656 2.149 7.84 ;
     RECT  2.149 9.664 2.165 9.696 ;
     RECT  2.165 9.664 2.219 10.912 ;
     RECT  1.653 1.984 2.229 2.912 ;
     RECT  2.149 4.288 2.229 7.84 ;
     RECT  1.899 22.656 2.339 24.096 ;
     RECT  2.229 1.984 2.483 7.84 ;
     RECT  2.339 22.656 2.531 23.392 ;
     RECT  2.485 12.416 2.539 12.448 ;
     RECT  2.005 14.208 2.579 18.272 ;
     RECT  2.483 4.288 2.723 7.84 ;
     RECT  2.579 14.208 2.859 16.032 ;
     RECT  2.483 1.984 2.915 2.784 ;
     RECT  2.723 7.424 2.915 7.84 ;
     RECT  1.715 20.288 2.915 20.32 ;
     RECT  2.531 22.656 2.915 22.688 ;
     RECT  1.387 27.072 2.963 27.104 ;
     RECT  2.915 7.424 3.299 7.648 ;
     RECT  2.859 15.104 3.299 16.032 ;
     RECT  3.299 7.424 3.443 7.456 ;
     RECT  2.219 10.176 3.443 10.912 ;
     RECT  2.723 4.288 3.755 5.664 ;
     RECT  3.443 10.176 3.957 10.848 ;
     RECT  3.957 9.984 4.011 10.848 ;
     RECT  2.579 17.344 4.011 18.272 ;
     RECT  3.755 5.12 4.595 5.664 ;
     RECT  4.011 17.344 4.595 17.632 ;
     RECT  4.011 9.984 5.123 10.016 ;
     RECT  4.595 5.12 5.171 5.152 ;
     RECT  4.595 17.6 5.459 17.632 ;
     RECT  2.915 2.752 8.579 2.784 ;
     RECT  3.299 16 9.923 16.032 ;
     RECT  4.501 20.032 10.883 20.064 ;
    LAYER M7 ;
     RECT  1.664 1.973 1.696 2.923 ;
     RECT  0.704 3.701 0.736 4.277 ;
     RECT  2.24 3.253 2.272 4.277 ;
     RECT  0.704 4.277 2.272 4.405 ;
     RECT  3.712 4.277 3.744 4.405 ;
     RECT  0.704 4.405 3.744 5.163 ;
     RECT  1.664 5.163 2.656 5.227 ;
     RECT  2.176 5.227 2.656 6.645 ;
     RECT  2.048 6.645 2.656 6.773 ;
     RECT  0.832 6.773 2.656 6.827 ;
     RECT  0.832 6.827 2.208 6.901 ;
     RECT  0.192 6.901 2.208 7.467 ;
     RECT  0.192 7.467 2.08 7.787 ;
     RECT  0.192 7.787 0.352 8.043 ;
     RECT  2.048 7.787 2.08 8.043 ;
     RECT  0.32 8.043 0.352 8.619 ;
     RECT  2.176 9.653 2.208 10.165 ;
     RECT  3.968 9.973 4 10.859 ;
     RECT  2.176 10.165 2.528 10.923 ;
     RECT  2.496 10.923 2.528 12.459 ;
     RECT  2.816 14.197 2.848 14.517 ;
     RECT  1.664 14.517 2.848 15.467 ;
     RECT  2.816 15.467 2.848 16.043 ;
     RECT  0.96 16.885 0.992 17.013 ;
     RECT  0.96 17.013 1.696 17.589 ;
     RECT  0.96 17.589 2.208 18.283 ;
     RECT  3.968 17.589 4 18.283 ;
     RECT  0.96 18.283 1.696 19.051 ;
     RECT  1.088 19.051 1.696 19.435 ;
     RECT  1.088 19.435 1.12 21.163 ;
     RECT  1.152 21.685 1.184 22.197 ;
     RECT  1.152 22.197 1.824 22.645 ;
     RECT  1.152 22.645 1.888 23.413 ;
     RECT  0.192 23.413 1.888 24.555 ;
     RECT  0.192 24.555 1.376 26.411 ;
     RECT  0.448 26.411 1.376 26.859 ;
  END
END ot_attn_bank_ew136
END LIBRARY
